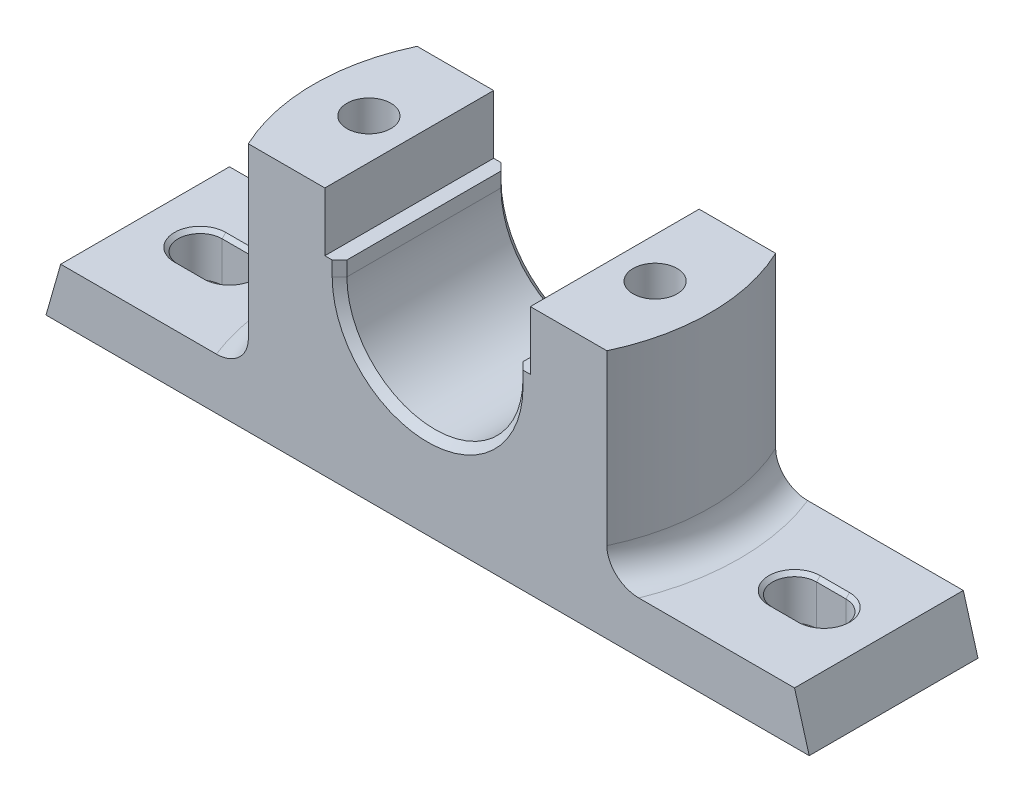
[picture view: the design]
ISO-10303-21;
HEADER;
FILE_DESCRIPTION(('STEP AP214'),'2;1');
FILE_NAME('part.step','',(''),(''),'','','');
FILE_SCHEMA(('AUTOMOTIVE_DESIGN { 1 0 10303 214 1 1 1 1 }'));
ENDSEC;
DATA;
#1=APPLICATION_CONTEXT('core data for automotive mechanical design processes');
#2=APPLICATION_PROTOCOL_DEFINITION('international standard','automotive_design',2000,#1);
#3=PRODUCT_CONTEXT('',#1,'mechanical');
#4=PRODUCT('Part','Part','',(#3));
#5=PRODUCT_RELATED_PRODUCT_CATEGORY('part','',(#4));
#6=PRODUCT_DEFINITION_FORMATION('','',#4);
#7=PRODUCT_DEFINITION_CONTEXT('part definition',#1,'design');
#8=PRODUCT_DEFINITION('design','',#6,#7);
#9=PRODUCT_DEFINITION_SHAPE('','',#8);
#10=(LENGTH_UNIT() NAMED_UNIT(*) SI_UNIT(.MILLI.,.METRE.));
#11=(NAMED_UNIT(*) PLANE_ANGLE_UNIT() SI_UNIT($,.RADIAN.));
#12=(NAMED_UNIT(*) SI_UNIT($,.STERADIAN.) SOLID_ANGLE_UNIT());
#13=UNCERTAINTY_MEASURE_WITH_UNIT(LENGTH_MEASURE(1.E-05),#10,'distance_accuracy_value','');
#14=(GEOMETRIC_REPRESENTATION_CONTEXT(3) GLOBAL_UNCERTAINTY_ASSIGNED_CONTEXT((#13)) GLOBAL_UNIT_ASSIGNED_CONTEXT((#10,
#11,#12)) REPRESENTATION_CONTEXT('',''));
#15=CARTESIAN_POINT('',(0.,0.,0.));
#16=DIRECTION('',(0.,0.,1.));
#17=DIRECTION('',(1.,0.,0.));
#18=AXIS2_PLACEMENT_3D('',#15,#16,#17);
#19=CARTESIAN_POINT('',(-97.5,2.,-17.5));
#20=DIRECTION('',(0.,-1.,0.));
#21=DIRECTION('',(0.,0.,-1.));
#22=AXIS2_PLACEMENT_3D('',#19,#20,#21);
#23=PLANE('',#22);
#24=CARTESIAN_POINT('',(85.,2.,0.));
#25=DIRECTION('',(0.,-1.,0.));
#26=DIRECTION('',(0.,0.,-1.));
#27=AXIS2_PLACEMENT_3D('',#24,#25,#26);
#28=CIRCLE('',#27,6.);
#29=CARTESIAN_POINT('',(85.,2.,-6.00000000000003));
#30=VERTEX_POINT('',#29);
#31=CARTESIAN_POINT('',(85.,2.,5.99999999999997));
#32=VERTEX_POINT('',#31);
#33=EDGE_CURVE('E338',#30,#32,#28,.T.);
#34=ORIENTED_EDGE('',*,*,#33,.F.);
#35=DIRECTION('',(1.,0.,0.));
#36=VECTOR('',#35,1.);
#37=CARTESIAN_POINT('',(-97.5,2.,-5.99999999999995));
#38=LINE('',#37,#36);
#39=CARTESIAN_POINT('',(77.,2.,-6.00000000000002));
#40=VERTEX_POINT('',#39);
#41=EDGE_CURVE('E320',#40,#30,#38,.T.);
#42=ORIENTED_EDGE('',*,*,#41,.F.);
#43=CARTESIAN_POINT('',(77.,2.,0.));
#44=DIRECTION('',(0.,-1.,0.));
#45=DIRECTION('',(0.,0.,-1.));
#46=AXIS2_PLACEMENT_3D('',#43,#44,#45);
#47=CIRCLE('',#46,6.);
#48=CARTESIAN_POINT('',(77.,2.,6.00000000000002));
#49=VERTEX_POINT('',#48);
#50=EDGE_CURVE('E332',#49,#40,#47,.T.);
#51=ORIENTED_EDGE('',*,*,#50,.F.);
#52=DIRECTION('',(-1.,0.,0.));
#53=VECTOR('',#52,1.);
#54=CARTESIAN_POINT('',(-97.5,2.,6.00000000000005));
#55=LINE('',#54,#53);
#56=EDGE_CURVE('E346',#32,#49,#55,.T.);
#57=ORIENTED_EDGE('',*,*,#56,.F.);
#58=EDGE_LOOP('',(#34,#42,#51,#57));
#59=FACE_BOUND('',#58,.T.);
#60=CARTESIAN_POINT('',(-77.,2.,0.));
#61=DIRECTION('',(0.,-1.,0.));
#62=DIRECTION('',(0.,0.,-1.));
#63=AXIS2_PLACEMENT_3D('',#60,#61,#62);
#64=CIRCLE('',#63,6.);
#65=CARTESIAN_POINT('',(-77.,2.,-6.));
#66=VERTEX_POINT('',#65);
#67=CARTESIAN_POINT('',(-77.,2.,6.));
#68=VERTEX_POINT('',#67);
#69=EDGE_CURVE('E370',#66,#68,#64,.T.);
#70=ORIENTED_EDGE('',*,*,#69,.F.);
#71=DIRECTION('',(1.,0.,0.));
#72=VECTOR('',#71,1.);
#73=CARTESIAN_POINT('',(-97.5,2.,-6.00000000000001));
#74=LINE('',#73,#72);
#75=CARTESIAN_POINT('',(-85.,2.,-6.00000000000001));
#76=VERTEX_POINT('',#75);
#77=EDGE_CURVE('E358',#76,#66,#74,.T.);
#78=ORIENTED_EDGE('',*,*,#77,.F.);
#79=CARTESIAN_POINT('',(-85.,2.,0.));
#80=DIRECTION('',(0.,-1.,0.));
#81=DIRECTION('',(0.,0.,-1.));
#82=AXIS2_PLACEMENT_3D('',#79,#80,#81);
#83=CIRCLE('',#82,6.);
#84=CARTESIAN_POINT('',(-85.,2.,5.99999999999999));
#85=VERTEX_POINT('',#84);
#86=EDGE_CURVE('E365',#85,#76,#83,.T.);
#87=ORIENTED_EDGE('',*,*,#86,.F.);
#88=DIRECTION('',(-1.,0.,0.));
#89=VECTOR('',#88,1.);
#90=CARTESIAN_POINT('',(-97.5,2.,5.99999999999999));
#91=LINE('',#90,#89);
#92=EDGE_CURVE('E368',#68,#85,#91,.T.);
#93=ORIENTED_EDGE('',*,*,#92,.F.);
#94=EDGE_LOOP('',(#70,#78,#87,#93));
#95=FACE_BOUND('',#94,.T.);
#96=DIRECTION('',(0.,0.,-1.));
#97=VECTOR('',#96,1.);
#98=CARTESIAN_POINT('',(-97.5,2.,17.5));
#99=LINE('',#98,#97);
#100=CARTESIAN_POINT('',(-97.5,2.,17.5));
#101=VERTEX_POINT('',#100);
#102=CARTESIAN_POINT('',(-97.5,2.,-17.5));
#103=VERTEX_POINT('',#102);
#104=EDGE_CURVE('E458',#101,#103,#99,.T.);
#105=ORIENTED_EDGE('',*,*,#104,.T.);
#106=DIRECTION('',(1.,0.,0.));
#107=VECTOR('',#106,1.);
#108=CARTESIAN_POINT('',(-97.5,2.,-17.5));
#109=LINE('',#108,#107);
#110=CARTESIAN_POINT('',(97.5,2.,-17.5));
#111=VERTEX_POINT('',#110);
#112=EDGE_CURVE('E461',#103,#111,#109,.T.);
#113=ORIENTED_EDGE('',*,*,#112,.T.);
#114=DIRECTION('',(0.,0.,1.));
#115=VECTOR('',#114,1.);
#116=CARTESIAN_POINT('',(97.5,2.,17.5));
#117=LINE('',#116,#115);
#118=CARTESIAN_POINT('',(97.5,2.,17.5));
#119=VERTEX_POINT('',#118);
#120=EDGE_CURVE('E464',#111,#119,#117,.T.);
#121=ORIENTED_EDGE('',*,*,#120,.T.);
#122=DIRECTION('',(-1.,0.,0.));
#123=VECTOR('',#122,1.);
#124=CARTESIAN_POINT('',(-97.5,2.,17.5));
#125=LINE('',#124,#123);
#126=EDGE_CURVE('E467',#119,#101,#125,.T.);
#127=ORIENTED_EDGE('',*,*,#126,.T.);
#128=EDGE_LOOP('',(#105,#113,#121,#127));
#129=FACE_BOUND('',#128,.T.);
#130=DIRECTION('',(0.,0.,-1.));
#131=VECTOR('',#130,1.);
#132=CARTESIAN_POINT('',(26.,2.,13.));
#133=LINE('',#132,#131);
#134=CARTESIAN_POINT('',(26.,2.,13.));
#135=VERTEX_POINT('',#134);
#136=CARTESIAN_POINT('',(26.,2.,-13.));
#137=VERTEX_POINT('',#136);
#138=EDGE_CURVE('E417',#135,#137,#133,.T.);
#139=ORIENTED_EDGE('',*,*,#138,.F.);
#140=DIRECTION('',(1.,0.,0.));
#141=VECTOR('',#140,1.);
#142=CARTESIAN_POINT('',(26.,2.,13.));
#143=LINE('',#142,#141);
#144=CARTESIAN_POINT('',(52.,2.,13.));
#145=VERTEX_POINT('',#144);
#146=EDGE_CURVE('E425',#135,#145,#143,.T.);
#147=ORIENTED_EDGE('',*,*,#146,.T.);
#148=DIRECTION('',(0.,0.,-1.));
#149=VECTOR('',#148,1.);
#150=CARTESIAN_POINT('',(52.,2.,13.));
#151=LINE('',#150,#149);
#152=CARTESIAN_POINT('',(52.,2.,-13.));
#153=VERTEX_POINT('',#152);
#154=EDGE_CURVE('E422',#145,#153,#151,.T.);
#155=ORIENTED_EDGE('',*,*,#154,.T.);
#156=DIRECTION('',(1.,0.,0.));
#157=VECTOR('',#156,1.);
#158=CARTESIAN_POINT('',(26.,2.,-13.));
#159=LINE('',#158,#157);
#160=EDGE_CURVE('E419',#137,#153,#159,.T.);
#161=ORIENTED_EDGE('',*,*,#160,.F.);
#162=EDGE_LOOP('',(#139,#147,#155,#161));
#163=FACE_BOUND('',#162,.T.);
#164=DIRECTION('',(-1.,0.,0.));
#165=VECTOR('',#164,1.);
#166=CARTESIAN_POINT('',(-26.,2.,13.));
#167=LINE('',#166,#165);
#168=CARTESIAN_POINT('',(-26.,2.,13.));
#169=VERTEX_POINT('',#168);
#170=CARTESIAN_POINT('',(-52.,2.,13.));
#171=VERTEX_POINT('',#170);
#172=EDGE_CURVE('E405',#169,#171,#167,.T.);
#173=ORIENTED_EDGE('',*,*,#172,.F.);
#174=DIRECTION('',(0.,0.,-1.));
#175=VECTOR('',#174,1.);
#176=CARTESIAN_POINT('',(-26.,2.,13.));
#177=LINE('',#176,#175);
#178=CARTESIAN_POINT('',(-26.,2.,-13.));
#179=VERTEX_POINT('',#178);
#180=EDGE_CURVE('E414',#169,#179,#177,.T.);
#181=ORIENTED_EDGE('',*,*,#180,.T.);
#182=DIRECTION('',(-1.,0.,0.));
#183=VECTOR('',#182,1.);
#184=CARTESIAN_POINT('',(-26.,2.,-13.));
#185=LINE('',#184,#183);
#186=CARTESIAN_POINT('',(-52.,2.,-13.));
#187=VERTEX_POINT('',#186);
#188=EDGE_CURVE('E411',#179,#187,#185,.T.);
#189=ORIENTED_EDGE('',*,*,#188,.T.);
#190=DIRECTION('',(0.,0.,-1.));
#191=VECTOR('',#190,1.);
#192=CARTESIAN_POINT('',(-52.,2.,13.));
#193=LINE('',#192,#191);
#194=EDGE_CURVE('E408',#171,#187,#193,.T.);
#195=ORIENTED_EDGE('',*,*,#194,.F.);
#196=EDGE_LOOP('',(#173,#181,#189,#195));
#197=FACE_BOUND('',#196,.T.);
#198=ADVANCED_FACE('F26',(#59,#95,#129,#163,#197),#23,.T.);
#199=CARTESIAN_POINT('',(54.,68.,23.));
#200=DIRECTION('',(0.,-1.,0.));
#201=DIRECTION('',(0.,0.,-1.));
#202=AXIS2_PLACEMENT_3D('',#199,#200,#201);
#203=PLANE('',#202);
#204=CARTESIAN_POINT('',(39.,68.,0.));
#205=DIRECTION('',(0.,-1.,0.));
#206=DIRECTION('',(0.,0.,-1.));
#207=AXIS2_PLACEMENT_3D('',#204,#205,#206);
#208=CIRCLE('',#207,6.);
#209=CARTESIAN_POINT('',(39.,68.,-6.));
#210=VERTEX_POINT('',#209);
#211=EDGE_CURVE('E375',#210,#210,#208,.T.);
#212=ORIENTED_EDGE('',*,*,#211,.T.);
#213=EDGE_LOOP('',(#212));
#214=FACE_BOUND('',#213,.T.);
#215=CARTESIAN_POINT('',(0.,68.,0.));
#216=DIRECTION('',(0.,1.,0.));
#217=DIRECTION('',(0.,0.,-1.));
#218=AXIS2_PLACEMENT_3D('',#215,#216,#217);
#219=CIRCLE('',#218,54.);
#220=CARTESIAN_POINT('',(48.8569340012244,68.,23.));
#221=VERTEX_POINT('',#220);
#222=CARTESIAN_POINT('',(48.8569340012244,68.,-23.));
#223=VERTEX_POINT('',#222);
#224=EDGE_CURVE('E480',#221,#223,#219,.T.);
#225=ORIENTED_EDGE('',*,*,#224,.T.);
#226=DIRECTION('',(-1.,0.,0.));
#227=VECTOR('',#226,1.);
#228=CARTESIAN_POINT('',(54.,68.,-23.));
#229=LINE('',#228,#227);
#230=CARTESIAN_POINT('',(28.,68.,-23.));
#231=VERTEX_POINT('',#230);
#232=EDGE_CURVE('E503',#223,#231,#229,.T.);
#233=ORIENTED_EDGE('',*,*,#232,.T.);
#234=DIRECTION('',(0.,0.,-1.));
#235=VECTOR('',#234,1.);
#236=CARTESIAN_POINT('',(28.,68.,23.));
#237=LINE('',#236,#235);
#238=CARTESIAN_POINT('',(28.,68.,23.));
#239=VERTEX_POINT('',#238);
#240=EDGE_CURVE('E569',#239,#231,#237,.T.);
#241=ORIENTED_EDGE('',*,*,#240,.F.);
#242=DIRECTION('',(-1.,0.,0.));
#243=VECTOR('',#242,1.);
#244=CARTESIAN_POINT('',(54.,68.,23.));
#245=LINE('',#244,#243);
#246=EDGE_CURVE('E529',#221,#239,#245,.T.);
#247=ORIENTED_EDGE('',*,*,#246,.F.);
#248=EDGE_LOOP('',(#225,#233,#241,#247));
#249=FACE_BOUND('',#248,.T.);
#250=ADVANCED_FACE('F694',(#214,#249),#203,.F.);
#251=CARTESIAN_POINT('',(-54.,68.,23.));
#252=DIRECTION('',(0.,-1.,0.));
#253=DIRECTION('',(1.,0.,0.));
#254=AXIS2_PLACEMENT_3D('',#251,#252,#253);
#255=PLANE('',#254);
#256=CARTESIAN_POINT('',(-39.,68.,0.));
#257=DIRECTION('',(0.,-1.,0.));
#258=DIRECTION('',(0.,0.,-1.));
#259=AXIS2_PLACEMENT_3D('',#256,#257,#258);
#260=CIRCLE('',#259,6.);
#261=CARTESIAN_POINT('',(-39.,68.,-6.00000000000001));
#262=VERTEX_POINT('',#261);
#263=EDGE_CURVE('E381',#262,#262,#260,.T.);
#264=ORIENTED_EDGE('',*,*,#263,.T.);
#265=EDGE_LOOP('',(#264));
#266=FACE_BOUND('',#265,.T.);
#267=CARTESIAN_POINT('',(0.,68.,0.));
#268=DIRECTION('',(0.,1.,0.));
#269=DIRECTION('',(0.,0.,1.));
#270=AXIS2_PLACEMENT_3D('',#267,#268,#269);
#271=CIRCLE('',#270,54.);
#272=CARTESIAN_POINT('',(-48.8569340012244,68.,-23.));
#273=VERTEX_POINT('',#272);
#274=CARTESIAN_POINT('',(-48.8569340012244,68.,23.));
#275=VERTEX_POINT('',#274);
#276=EDGE_CURVE('E485',#273,#275,#271,.T.);
#277=ORIENTED_EDGE('',*,*,#276,.T.);
#278=DIRECTION('',(-1.,0.,0.));
#279=VECTOR('',#278,1.);
#280=CARTESIAN_POINT('',(-54.,68.,23.));
#281=LINE('',#280,#279);
#282=CARTESIAN_POINT('',(-28.,68.,23.));
#283=VERTEX_POINT('',#282);
#284=EDGE_CURVE('E540',#283,#275,#281,.T.);
#285=ORIENTED_EDGE('',*,*,#284,.F.);
#286=DIRECTION('',(0.,0.,-1.));
#287=VECTOR('',#286,1.);
#288=CARTESIAN_POINT('',(-28.,68.,23.));
#289=LINE('',#288,#287);
#290=CARTESIAN_POINT('',(-28.,68.,-23.));
#291=VERTEX_POINT('',#290);
#292=EDGE_CURVE('E548',#283,#291,#289,.T.);
#293=ORIENTED_EDGE('',*,*,#292,.T.);
#294=DIRECTION('',(-1.,0.,0.));
#295=VECTOR('',#294,1.);
#296=CARTESIAN_POINT('',(-54.,68.,-23.));
#297=LINE('',#296,#295);
#298=EDGE_CURVE('E514',#291,#273,#297,.T.);
#299=ORIENTED_EDGE('',*,*,#298,.T.);
#300=EDGE_LOOP('',(#277,#285,#293,#299));
#301=FACE_BOUND('',#300,.T.);
#302=ADVANCED_FACE('F701',(#266,#301),#255,.F.);
#303=CARTESIAN_POINT('',(-104.,0.,23.));
#304=DIRECTION('',(0.961523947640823,-0.27472112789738,0.));
#305=DIRECTION('',(0.27472112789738,0.961523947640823,0.));
#306=AXIS2_PLACEMENT_3D('',#303,#304,#305);
#307=PLANE('',#306);
#308=DIRECTION('',(-0.27472112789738,-0.961523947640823,0.));
#309=VECTOR('',#308,1.);
#310=CARTESIAN_POINT('',(-104.,0.,-23.));
#311=LINE('',#310,#309);
#312=CARTESIAN_POINT('',(-100.,14.,-23.));
#313=VERTEX_POINT('',#312);
#314=CARTESIAN_POINT('',(-104.,0.,-23.));
#315=VERTEX_POINT('',#314);
#316=EDGE_CURVE('E493',#313,#315,#311,.T.);
#317=ORIENTED_EDGE('',*,*,#316,.T.);
#318=DIRECTION('',(0.,0.,-1.));
#319=VECTOR('',#318,1.);
#320=CARTESIAN_POINT('',(-104.,0.,23.));
#321=LINE('',#320,#319);
#322=CARTESIAN_POINT('',(-104.,0.,23.));
#323=VERTEX_POINT('',#322);
#324=EDGE_CURVE('E578',#323,#315,#321,.T.);
#325=ORIENTED_EDGE('',*,*,#324,.F.);
#326=DIRECTION('',(-0.27472112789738,-0.961523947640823,0.));
#327=VECTOR('',#326,1.);
#328=CARTESIAN_POINT('',(-104.,0.,23.));
#329=LINE('',#328,#327);
#330=CARTESIAN_POINT('',(-100.,14.,23.));
#331=VERTEX_POINT('',#330);
#332=EDGE_CURVE('E519',#331,#323,#329,.T.);
#333=ORIENTED_EDGE('',*,*,#332,.F.);
#334=DIRECTION('',(0.,0.,-1.));
#335=VECTOR('',#334,1.);
#336=CARTESIAN_POINT('',(-100.,14.,23.));
#337=LINE('',#336,#335);
#338=EDGE_CURVE('E545',#331,#313,#337,.T.);
#339=ORIENTED_EDGE('',*,*,#338,.T.);
#340=EDGE_LOOP('',(#317,#325,#333,#339));
#341=FACE_BOUND('',#340,.T.);
#342=ADVANCED_FACE('F28',(#341),#307,.F.);
#343=CARTESIAN_POINT('',(-104.,0.,23.));
#344=DIRECTION('',(0.,1.,0.));
#345=DIRECTION('',(0.,0.,1.));
#346=AXIS2_PLACEMENT_3D('',#343,#344,#345);
#347=PLANE('',#346);
#348=DIRECTION('',(1.,0.,0.));
#349=VECTOR('',#348,1.);
#350=CARTESIAN_POINT('',(-97.5,0.,-17.5));
#351=LINE('',#350,#349);
#352=CARTESIAN_POINT('',(-97.5,0.,-17.5));
#353=VERTEX_POINT('',#352);
#354=CARTESIAN_POINT('',(97.5,0.,-17.5));
#355=VERTEX_POINT('',#354);
#356=EDGE_CURVE('E449',#353,#355,#351,.T.);
#357=ORIENTED_EDGE('',*,*,#356,.F.);
#358=DIRECTION('',(0.,0.,-1.));
#359=VECTOR('',#358,1.);
#360=CARTESIAN_POINT('',(-97.5,0.,17.5));
#361=LINE('',#360,#359);
#362=CARTESIAN_POINT('',(-97.5,0.,17.5));
#363=VERTEX_POINT('',#362);
#364=EDGE_CURVE('E441',#363,#353,#361,.T.);
#365=ORIENTED_EDGE('',*,*,#364,.F.);
#366=DIRECTION('',(-1.,0.,0.));
#367=VECTOR('',#366,1.);
#368=CARTESIAN_POINT('',(-97.5,0.,17.5));
#369=LINE('',#368,#367);
#370=CARTESIAN_POINT('',(97.5,0.,17.5));
#371=VERTEX_POINT('',#370);
#372=EDGE_CURVE('E455',#371,#363,#369,.T.);
#373=ORIENTED_EDGE('',*,*,#372,.F.);
#374=DIRECTION('',(0.,0.,1.));
#375=VECTOR('',#374,1.);
#376=CARTESIAN_POINT('',(97.5,0.,17.5));
#377=LINE('',#376,#375);
#378=EDGE_CURVE('E452',#355,#371,#377,.T.);
#379=ORIENTED_EDGE('',*,*,#378,.F.);
#380=EDGE_LOOP('',(#357,#365,#373,#379));
#381=FACE_BOUND('',#380,.T.);
#382=DIRECTION('',(1.,0.,0.));
#383=VECTOR('',#382,1.);
#384=CARTESIAN_POINT('',(-104.,0.,-23.));
#385=LINE('',#384,#383);
#386=CARTESIAN_POINT('',(104.,0.,-23.));
#387=VERTEX_POINT('',#386);
#388=EDGE_CURVE('E496',#315,#387,#385,.T.);
#389=ORIENTED_EDGE('',*,*,#388,.T.);
#390=DIRECTION('',(0.,0.,-1.));
#391=VECTOR('',#390,1.);
#392=CARTESIAN_POINT('',(104.,0.,23.));
#393=LINE('',#392,#391);
#394=CARTESIAN_POINT('',(104.,0.,23.));
#395=VERTEX_POINT('',#394);
#396=EDGE_CURVE('E575',#395,#387,#393,.T.);
#397=ORIENTED_EDGE('',*,*,#396,.F.);
#398=DIRECTION('',(1.,0.,0.));
#399=VECTOR('',#398,1.);
#400=CARTESIAN_POINT('',(-104.,0.,23.));
#401=LINE('',#400,#399);
#402=EDGE_CURVE('E522',#323,#395,#401,.T.);
#403=ORIENTED_EDGE('',*,*,#402,.F.);
#404=ORIENTED_EDGE('',*,*,#324,.T.);
#405=EDGE_LOOP('',(#389,#397,#403,#404));
#406=FACE_BOUND('',#405,.T.);
#407=ADVANCED_FACE('F753',(#381,#406),#347,.F.);
#408=CARTESIAN_POINT('',(104.,0.,23.));
#409=DIRECTION('',(-0.961523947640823,-0.274721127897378,0.));
#410=DIRECTION('',(0.274721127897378,-0.961523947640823,0.));
#411=AXIS2_PLACEMENT_3D('',#408,#409,#410);
#412=PLANE('',#411);
#413=DIRECTION('',(-0.274721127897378,0.961523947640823,0.));
#414=VECTOR('',#413,1.);
#415=CARTESIAN_POINT('',(104.,0.,-23.));
#416=LINE('',#415,#414);
#417=CARTESIAN_POINT('',(100.,14.,-23.));
#418=VERTEX_POINT('',#417);
#419=EDGE_CURVE('E498',#387,#418,#416,.T.);
#420=ORIENTED_EDGE('',*,*,#419,.T.);
#421=DIRECTION('',(0.,0.,-1.));
#422=VECTOR('',#421,1.);
#423=CARTESIAN_POINT('',(100.,14.,23.));
#424=LINE('',#423,#422);
#425=CARTESIAN_POINT('',(100.,14.,23.));
#426=VERTEX_POINT('',#425);
#427=EDGE_CURVE('E572',#426,#418,#424,.T.);
#428=ORIENTED_EDGE('',*,*,#427,.F.);
#429=DIRECTION('',(-0.274721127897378,0.961523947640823,0.));
#430=VECTOR('',#429,1.);
#431=CARTESIAN_POINT('',(104.,0.,23.));
#432=LINE('',#431,#430);
#433=EDGE_CURVE('E524',#395,#426,#432,.T.);
#434=ORIENTED_EDGE('',*,*,#433,.F.);
#435=ORIENTED_EDGE('',*,*,#396,.T.);
#436=EDGE_LOOP('',(#420,#428,#434,#435));
#437=FACE_BOUND('',#436,.T.);
#438=ADVANCED_FACE('F756',(#437),#412,.F.);
#439=CARTESIAN_POINT('',(100.,14.,23.));
#440=DIRECTION('',(0.,-1.,0.));
#441=DIRECTION('',(1.,0.,0.));
#442=AXIS2_PLACEMENT_3D('',#439,#440,#441);
#443=PLANE('',#442);
#444=CARTESIAN_POINT('',(77.,14.,0.));
#445=DIRECTION('',(0.,-1.,0.));
#446=DIRECTION('',(1.,0.,0.));
#447=AXIS2_PLACEMENT_3D('',#444,#445,#446);
#448=CIRCLE('',#447,7.);
#449=CARTESIAN_POINT('',(77.,14.,6.99999999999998));
#450=VERTEX_POINT('',#449);
#451=CARTESIAN_POINT('',(77.,14.,-6.99999999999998));
#452=VERTEX_POINT('',#451);
#453=EDGE_CURVE('E885',#450,#452,#448,.T.);
#454=ORIENTED_EDGE('',*,*,#453,.T.);
#455=DIRECTION('',(1.,0.,0.));
#456=VECTOR('',#455,1.);
#457=CARTESIAN_POINT('',(100.,14.,-7.00000000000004));
#458=LINE('',#457,#456);
#459=CARTESIAN_POINT('',(85.,14.,-6.99999999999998));
#460=VERTEX_POINT('',#459);
#461=EDGE_CURVE('E889',#452,#460,#458,.T.);
#462=ORIENTED_EDGE('',*,*,#461,.T.);
#463=CARTESIAN_POINT('',(85.,14.,0.));
#464=DIRECTION('',(0.,-1.,0.));
#465=DIRECTION('',(1.,0.,0.));
#466=AXIS2_PLACEMENT_3D('',#463,#464,#465);
#467=CIRCLE('',#466,7.);
#468=CARTESIAN_POINT('',(85.,14.,6.99999999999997));
#469=VERTEX_POINT('',#468);
#470=EDGE_CURVE('E890',#460,#469,#467,.T.);
#471=ORIENTED_EDGE('',*,*,#470,.T.);
#472=DIRECTION('',(-1.,0.,0.));
#473=VECTOR('',#472,1.);
#474=CARTESIAN_POINT('',(100.,14.,6.99999999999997));
#475=LINE('',#474,#473);
#476=EDGE_CURVE('E893',#469,#450,#475,.T.);
#477=ORIENTED_EDGE('',*,*,#476,.T.);
#478=EDGE_LOOP('',(#454,#462,#471,#477));
#479=FACE_BOUND('',#478,.T.);
#480=DIRECTION('',(-1.,0.,0.));
#481=VECTOR('',#480,1.);
#482=CARTESIAN_POINT('',(100.,14.,-23.));
#483=LINE('',#482,#481);
#484=CARTESIAN_POINT('',(57.5760366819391,14.,-23.));
#485=VERTEX_POINT('',#484);
#486=EDGE_CURVE('E500',#418,#485,#483,.T.);
#487=ORIENTED_EDGE('',*,*,#486,.T.);
#488=CARTESIAN_POINT('',(0.,14.,0.));
#489=DIRECTION('',(0.,-1.,0.));
#490=DIRECTION('',(1.,0.,0.));
#491=AXIS2_PLACEMENT_3D('',#488,#489,#490);
#492=CIRCLE('',#491,62.);
#493=CARTESIAN_POINT('',(57.5760366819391,14.,23.));
#494=VERTEX_POINT('',#493);
#495=EDGE_CURVE('E589',#485,#494,#492,.T.);
#496=ORIENTED_EDGE('',*,*,#495,.T.);
#497=DIRECTION('',(-1.,0.,0.));
#498=VECTOR('',#497,1.);
#499=CARTESIAN_POINT('',(100.,14.,23.));
#500=LINE('',#499,#498);
#501=EDGE_CURVE('E526',#426,#494,#500,.T.);
#502=ORIENTED_EDGE('',*,*,#501,.F.);
#503=ORIENTED_EDGE('',*,*,#427,.T.);
#504=EDGE_LOOP('',(#487,#496,#502,#503));
#505=FACE_BOUND('',#504,.T.);
#506=ADVANCED_FACE('F760',(#479,#505),#443,.F.);
#507=CARTESIAN_POINT('',(28.,68.,23.));
#508=DIRECTION('',(1.,0.,0.));
#509=DIRECTION('',(0.,0.,-1.));
#510=AXIS2_PLACEMENT_3D('',#507,#508,#509);
#511=PLANE('',#510);
#512=DIRECTION('',(0.,-1.,0.));
#513=VECTOR('',#512,1.);
#514=CARTESIAN_POINT('',(28.,68.,-23.));
#515=LINE('',#514,#513);
#516=CARTESIAN_POINT('',(28.,52.,-23.));
#517=VERTEX_POINT('',#516);
#518=EDGE_CURVE('E505',#231,#517,#515,.T.);
#519=ORIENTED_EDGE('',*,*,#518,.T.);
#520=DIRECTION('',(0.,0.,-1.));
#521=VECTOR('',#520,1.);
#522=CARTESIAN_POINT('',(28.,52.,23.));
#523=LINE('',#522,#521);
#524=CARTESIAN_POINT('',(28.,52.,23.));
#525=VERTEX_POINT('',#524);
#526=EDGE_CURVE('E566',#525,#517,#523,.T.);
#527=ORIENTED_EDGE('',*,*,#526,.F.);
#528=DIRECTION('',(0.,-1.,0.));
#529=VECTOR('',#528,1.);
#530=CARTESIAN_POINT('',(28.,68.,23.));
#531=LINE('',#530,#529);
#532=EDGE_CURVE('E531',#239,#525,#531,.T.);
#533=ORIENTED_EDGE('',*,*,#532,.F.);
#534=ORIENTED_EDGE('',*,*,#240,.T.);
#535=EDGE_LOOP('',(#519,#527,#533,#534));
#536=FACE_BOUND('',#535,.T.);
#537=ADVANCED_FACE('F775',(#536),#511,.F.);
#538=CARTESIAN_POINT('',(28.,52.,23.));
#539=DIRECTION('',(0.,-1.,0.));
#540=DIRECTION('',(1.,0.,0.));
#541=AXIS2_PLACEMENT_3D('',#538,#539,#540);
#542=PLANE('',#541);
#543=DIRECTION('',(-1.,0.,0.));
#544=VECTOR('',#543,1.);
#545=CARTESIAN_POINT('',(28.,52.,-23.));
#546=LINE('',#545,#544);
#547=CARTESIAN_POINT('',(26.,52.,-23.));
#548=VERTEX_POINT('',#547);
#549=EDGE_CURVE('E507',#517,#548,#546,.T.);
#550=ORIENTED_EDGE('',*,*,#549,.T.);
#551=DIRECTION('',(0.707106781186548,0.,-0.707106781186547));
#552=VECTOR('',#551,1.);
#553=CARTESIAN_POINT('',(24.,52.,-21.));
#554=LINE('',#553,#552);
#555=CARTESIAN_POINT('',(24.,52.,-21.));
#556=VERTEX_POINT('',#555);
#557=EDGE_CURVE('E782',#548,#556,#554,.F.);
#558=ORIENTED_EDGE('',*,*,#557,.T.);
#559=DIRECTION('',(0.,0.,-1.));
#560=VECTOR('',#559,1.);
#561=CARTESIAN_POINT('',(24.,52.,23.));
#562=LINE('',#561,#560);
#563=CARTESIAN_POINT('',(24.,52.,21.));
#564=VERTEX_POINT('',#563);
#565=EDGE_CURVE('E563',#564,#556,#562,.T.);
#566=ORIENTED_EDGE('',*,*,#565,.F.);
#567=DIRECTION('',(0.707106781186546,0.,0.707106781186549));
#568=VECTOR('',#567,1.);
#569=CARTESIAN_POINT('',(26.,52.,23.));
#570=LINE('',#569,#568);
#571=CARTESIAN_POINT('',(26.,52.,23.));
#572=VERTEX_POINT('',#571);
#573=EDGE_CURVE('E779',#564,#572,#570,.T.);
#574=ORIENTED_EDGE('',*,*,#573,.T.);
#575=DIRECTION('',(-1.,0.,0.));
#576=VECTOR('',#575,1.);
#577=CARTESIAN_POINT('',(28.,52.,23.));
#578=LINE('',#577,#576);
#579=EDGE_CURVE('E533',#525,#572,#578,.T.);
#580=ORIENTED_EDGE('',*,*,#579,.F.);
#581=ORIENTED_EDGE('',*,*,#526,.T.);
#582=EDGE_LOOP('',(#550,#558,#566,#574,#580,#581));
#583=FACE_BOUND('',#582,.T.);
#584=ADVANCED_FACE('F1199',(#583),#542,.F.);
#585=CARTESIAN_POINT('',(24.,52.,23.));
#586=DIRECTION('',(1.,0.,0.));
#587=DIRECTION('',(0.,1.,0.));
#588=AXIS2_PLACEMENT_3D('',#585,#586,#587);
#589=PLANE('',#588);
#590=ORIENTED_EDGE('',*,*,#565,.T.);
#591=DIRECTION('',(0.,-1.,0.));
#592=VECTOR('',#591,1.);
#593=CARTESIAN_POINT('',(24.,52.,-21.));
#594=LINE('',#593,#592);
#595=CARTESIAN_POINT('',(24.,48.,-21.));
#596=VERTEX_POINT('',#595);
#597=EDGE_CURVE('E831',#556,#596,#594,.T.);
#598=ORIENTED_EDGE('',*,*,#597,.T.);
#599=DIRECTION('',(0.,0.,-1.));
#600=VECTOR('',#599,1.);
#601=CARTESIAN_POINT('',(24.,48.,23.));
#602=LINE('',#601,#600);
#603=CARTESIAN_POINT('',(24.,48.,21.));
#604=VERTEX_POINT('',#603);
#605=EDGE_CURVE('E560',#604,#596,#602,.T.);
#606=ORIENTED_EDGE('',*,*,#605,.F.);
#607=DIRECTION('',(0.,1.,0.));
#608=VECTOR('',#607,1.);
#609=CARTESIAN_POINT('',(24.,52.,21.));
#610=LINE('',#609,#608);
#611=EDGE_CURVE('E780',#604,#564,#610,.T.);
#612=ORIENTED_EDGE('',*,*,#611,.T.);
#613=EDGE_LOOP('',(#590,#598,#606,#612));
#614=FACE_BOUND('',#613,.T.);
#615=ADVANCED_FACE('F832',(#614),#589,.F.);
#616=CARTESIAN_POINT('',(0.,48.,23.));
#617=DIRECTION('',(0.,0.,-1.));
#618=DIRECTION('',(-1.,0.,0.));
#619=AXIS2_PLACEMENT_3D('',#616,#617,#618);
#620=CYLINDRICAL_SURFACE('',#619,24.);
#621=ORIENTED_EDGE('',*,*,#605,.T.);
#622=CARTESIAN_POINT('',(0.,48.,-21.));
#623=DIRECTION('',(0.,0.,1.));
#624=DIRECTION('',(1.,0.,0.));
#625=AXIS2_PLACEMENT_3D('',#622,#623,#624);
#626=CIRCLE('',#625,24.);
#627=CARTESIAN_POINT('',(-24.,48.,-21.));
#628=VERTEX_POINT('',#627);
#629=EDGE_CURVE('E800',#596,#628,#626,.F.);
#630=ORIENTED_EDGE('',*,*,#629,.T.);
#631=DIRECTION('',(0.,0.,-1.));
#632=VECTOR('',#631,1.);
#633=CARTESIAN_POINT('',(-24.,48.,23.));
#634=LINE('',#633,#632);
#635=CARTESIAN_POINT('',(-24.,48.,21.));
#636=VERTEX_POINT('',#635);
#637=EDGE_CURVE('E557',#636,#628,#634,.T.);
#638=ORIENTED_EDGE('',*,*,#637,.F.);
#639=CARTESIAN_POINT('',(0.,48.,21.));
#640=DIRECTION('',(0.,0.,1.));
#641=DIRECTION('',(1.,0.,0.));
#642=AXIS2_PLACEMENT_3D('',#639,#640,#641);
#643=CIRCLE('',#642,24.);
#644=EDGE_CURVE('E798',#636,#604,#643,.T.);
#645=ORIENTED_EDGE('',*,*,#644,.T.);
#646=EDGE_LOOP('',(#621,#630,#638,#645));
#647=FACE_BOUND('',#646,.T.);
#648=ADVANCED_FACE('F819',(#647),#620,.F.);
#649=CARTESIAN_POINT('',(-24.,52.,23.));
#650=DIRECTION('',(-1.,0.,0.));
#651=DIRECTION('',(0.,-1.,0.));
#652=AXIS2_PLACEMENT_3D('',#649,#650,#651);
#653=PLANE('',#652);
#654=ORIENTED_EDGE('',*,*,#637,.T.);
#655=DIRECTION('',(0.,1.,0.));
#656=VECTOR('',#655,1.);
#657=CARTESIAN_POINT('',(-24.,52.,-21.));
#658=LINE('',#657,#656);
#659=CARTESIAN_POINT('',(-24.,52.,-21.));
#660=VERTEX_POINT('',#659);
#661=EDGE_CURVE('E792',#628,#660,#658,.T.);
#662=ORIENTED_EDGE('',*,*,#661,.T.);
#663=DIRECTION('',(0.,0.,-1.));
#664=VECTOR('',#663,1.);
#665=CARTESIAN_POINT('',(-24.,52.,23.));
#666=LINE('',#665,#664);
#667=CARTESIAN_POINT('',(-24.,52.,21.));
#668=VERTEX_POINT('',#667);
#669=EDGE_CURVE('E554',#668,#660,#666,.T.);
#670=ORIENTED_EDGE('',*,*,#669,.F.);
#671=DIRECTION('',(0.,-1.,0.));
#672=VECTOR('',#671,1.);
#673=CARTESIAN_POINT('',(-24.,48.,21.));
#674=LINE('',#673,#672);
#675=EDGE_CURVE('E785',#668,#636,#674,.T.);
#676=ORIENTED_EDGE('',*,*,#675,.T.);
#677=EDGE_LOOP('',(#654,#662,#670,#676));
#678=FACE_BOUND('',#677,.T.);
#679=ADVANCED_FACE('F816',(#678),#653,.F.);
#680=CARTESIAN_POINT('',(-28.,52.,23.));
#681=DIRECTION('',(0.,-1.,0.));
#682=DIRECTION('',(1.,0.,0.));
#683=AXIS2_PLACEMENT_3D('',#680,#681,#682);
#684=PLANE('',#683);
#685=ORIENTED_EDGE('',*,*,#669,.T.);
#686=DIRECTION('',(0.707106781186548,0.,0.707106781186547));
#687=VECTOR('',#686,1.);
#688=CARTESIAN_POINT('',(-24.,52.,-21.));
#689=LINE('',#688,#687);
#690=CARTESIAN_POINT('',(-26.,52.,-23.));
#691=VERTEX_POINT('',#690);
#692=EDGE_CURVE('E796',#660,#691,#689,.F.);
#693=ORIENTED_EDGE('',*,*,#692,.T.);
#694=DIRECTION('',(-1.,0.,0.));
#695=VECTOR('',#694,1.);
#696=CARTESIAN_POINT('',(-28.,52.,-23.));
#697=LINE('',#696,#695);
#698=CARTESIAN_POINT('',(-28.,52.,-23.));
#699=VERTEX_POINT('',#698);
#700=EDGE_CURVE('E510',#691,#699,#697,.T.);
#701=ORIENTED_EDGE('',*,*,#700,.T.);
#702=DIRECTION('',(0.,0.,-1.));
#703=VECTOR('',#702,1.);
#704=CARTESIAN_POINT('',(-28.,52.,23.));
#705=LINE('',#704,#703);
#706=CARTESIAN_POINT('',(-28.,52.,23.));
#707=VERTEX_POINT('',#706);
#708=EDGE_CURVE('E551',#707,#699,#705,.T.);
#709=ORIENTED_EDGE('',*,*,#708,.F.);
#710=DIRECTION('',(-1.,0.,0.));
#711=VECTOR('',#710,1.);
#712=CARTESIAN_POINT('',(-28.,52.,23.));
#713=LINE('',#712,#711);
#714=CARTESIAN_POINT('',(-26.,52.,23.));
#715=VERTEX_POINT('',#714);
#716=EDGE_CURVE('E536',#715,#707,#713,.T.);
#717=ORIENTED_EDGE('',*,*,#716,.F.);
#718=DIRECTION('',(0.707106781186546,0.,-0.707106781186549));
#719=VECTOR('',#718,1.);
#720=CARTESIAN_POINT('',(-26.,52.,23.));
#721=LINE('',#720,#719);
#722=EDGE_CURVE('E794',#715,#668,#721,.T.);
#723=ORIENTED_EDGE('',*,*,#722,.T.);
#724=EDGE_LOOP('',(#685,#693,#701,#709,#717,#723));
#725=FACE_BOUND('',#724,.T.);
#726=ADVANCED_FACE('F808',(#725),#684,.F.);
#727=CARTESIAN_POINT('',(-28.,68.,23.));
#728=DIRECTION('',(-1.,0.,0.));
#729=DIRECTION('',(0.,0.,1.));
#730=AXIS2_PLACEMENT_3D('',#727,#728,#729);
#731=PLANE('',#730);
#732=DIRECTION('',(0.,1.,0.));
#733=VECTOR('',#732,1.);
#734=CARTESIAN_POINT('',(-28.,68.,-23.));
#735=LINE('',#734,#733);
#736=EDGE_CURVE('E512',#699,#291,#735,.T.);
#737=ORIENTED_EDGE('',*,*,#736,.T.);
#738=ORIENTED_EDGE('',*,*,#292,.F.);
#739=DIRECTION('',(0.,1.,0.));
#740=VECTOR('',#739,1.);
#741=CARTESIAN_POINT('',(-28.,68.,23.));
#742=LINE('',#741,#740);
#743=EDGE_CURVE('E538',#707,#283,#742,.T.);
#744=ORIENTED_EDGE('',*,*,#743,.F.);
#745=ORIENTED_EDGE('',*,*,#708,.T.);
#746=EDGE_LOOP('',(#737,#738,#744,#745));
#747=FACE_BOUND('',#746,.T.);
#748=ADVANCED_FACE('F1179',(#747),#731,.F.);
#749=CARTESIAN_POINT('',(-100.,14.,23.));
#750=DIRECTION('',(0.,-1.,0.));
#751=DIRECTION('',(1.,0.,0.));
#752=AXIS2_PLACEMENT_3D('',#749,#750,#751);
#753=PLANE('',#752);
#754=CARTESIAN_POINT('',(-85.,14.,0.));
#755=DIRECTION('',(0.,-1.,0.));
#756=DIRECTION('',(1.,0.,0.));
#757=AXIS2_PLACEMENT_3D('',#754,#755,#756);
#758=CIRCLE('',#757,6.99999999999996);
#759=CARTESIAN_POINT('',(-85.,14.,6.99999999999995));
#760=VERTEX_POINT('',#759);
#761=CARTESIAN_POINT('',(-85.,14.,-6.99999999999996));
#762=VERTEX_POINT('',#761);
#763=EDGE_CURVE('E910',#760,#762,#758,.T.);
#764=ORIENTED_EDGE('',*,*,#763,.T.);
#765=DIRECTION('',(1.,0.,0.));
#766=VECTOR('',#765,1.);
#767=CARTESIAN_POINT('',(-100.,14.,-6.99999999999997));
#768=LINE('',#767,#766);
#769=CARTESIAN_POINT('',(-77.,14.,-6.99999999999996));
#770=VERTEX_POINT('',#769);
#771=EDGE_CURVE('E907',#762,#770,#768,.T.);
#772=ORIENTED_EDGE('',*,*,#771,.T.);
#773=CARTESIAN_POINT('',(-77.,14.,0.));
#774=DIRECTION('',(0.,-1.,0.));
#775=DIRECTION('',(1.,0.,0.));
#776=AXIS2_PLACEMENT_3D('',#773,#774,#775);
#777=CIRCLE('',#776,6.99999999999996);
#778=CARTESIAN_POINT('',(-77.,14.,6.99999999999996));
#779=VERTEX_POINT('',#778);
#780=EDGE_CURVE('E912',#770,#779,#777,.T.);
#781=ORIENTED_EDGE('',*,*,#780,.T.);
#782=DIRECTION('',(-1.,0.,0.));
#783=VECTOR('',#782,1.);
#784=CARTESIAN_POINT('',(-100.,14.,6.99999999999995));
#785=LINE('',#784,#783);
#786=EDGE_CURVE('E913',#779,#760,#785,.T.);
#787=ORIENTED_EDGE('',*,*,#786,.T.);
#788=EDGE_LOOP('',(#764,#772,#781,#787));
#789=FACE_BOUND('',#788,.T.);
#790=DIRECTION('',(-1.,0.,0.));
#791=VECTOR('',#790,1.);
#792=CARTESIAN_POINT('',(-100.,14.,23.));
#793=LINE('',#792,#791);
#794=CARTESIAN_POINT('',(-57.5760366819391,14.,23.));
#795=VERTEX_POINT('',#794);
#796=EDGE_CURVE('E543',#795,#331,#793,.T.);
#797=ORIENTED_EDGE('',*,*,#796,.F.);
#798=CARTESIAN_POINT('',(0.,14.,0.));
#799=DIRECTION('',(0.,-1.,0.));
#800=DIRECTION('',(1.,0.,0.));
#801=AXIS2_PLACEMENT_3D('',#798,#799,#800);
#802=CIRCLE('',#801,62.);
#803=CARTESIAN_POINT('',(-57.5760366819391,14.,-23.));
#804=VERTEX_POINT('',#803);
#805=EDGE_CURVE('E584',#795,#804,#802,.T.);
#806=ORIENTED_EDGE('',*,*,#805,.T.);
#807=DIRECTION('',(-1.,0.,0.));
#808=VECTOR('',#807,1.);
#809=CARTESIAN_POINT('',(-100.,14.,-23.));
#810=LINE('',#809,#808);
#811=EDGE_CURVE('E517',#804,#313,#810,.T.);
#812=ORIENTED_EDGE('',*,*,#811,.T.);
#813=ORIENTED_EDGE('',*,*,#338,.F.);
#814=EDGE_LOOP('',(#797,#806,#812,#813));
#815=FACE_BOUND('',#814,.T.);
#816=ADVANCED_FACE('F613',(#789,#815),#753,.F.);
#817=CARTESIAN_POINT('',(0.,48.,23.));
#818=DIRECTION('',(0.,0.,1.));
#819=DIRECTION('',(1.,0.,0.));
#820=AXIS2_PLACEMENT_3D('',#817,#818,#819);
#821=PLANE('',#820);
#822=ORIENTED_EDGE('',*,*,#579,.T.);
#823=DIRECTION('',(0.,-1.,0.));
#824=VECTOR('',#823,1.);
#825=CARTESIAN_POINT('',(26.,48.,23.));
#826=LINE('',#825,#824);
#827=CARTESIAN_POINT('',(26.,48.,23.));
#828=VERTEX_POINT('',#827);
#829=EDGE_CURVE('E11',#572,#828,#826,.T.);
#830=ORIENTED_EDGE('',*,*,#829,.T.);
#831=CARTESIAN_POINT('',(0.,48.,23.));
#832=DIRECTION('',(0.,0.,1.));
#833=DIRECTION('',(1.,0.,0.));
#834=AXIS2_PLACEMENT_3D('',#831,#832,#833);
#835=CIRCLE('',#834,26.);
#836=CARTESIAN_POINT('',(-26.,48.,23.));
#837=VERTEX_POINT('',#836);
#838=EDGE_CURVE('E40',#828,#837,#835,.F.);
#839=ORIENTED_EDGE('',*,*,#838,.T.);
#840=DIRECTION('',(0.,1.,0.));
#841=VECTOR('',#840,1.);
#842=CARTESIAN_POINT('',(-26.,52.,23.));
#843=LINE('',#842,#841);
#844=EDGE_CURVE('E34',#837,#715,#843,.T.);
#845=ORIENTED_EDGE('',*,*,#844,.T.);
#846=ORIENTED_EDGE('',*,*,#716,.T.);
#847=ORIENTED_EDGE('',*,*,#743,.T.);
#848=ORIENTED_EDGE('',*,*,#284,.T.);
#849=DIRECTION('',(0.,1.,0.));
#850=VECTOR('',#849,1.);
#851=CARTESIAN_POINT('',(-48.8569340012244,-999932.,23.));
#852=LINE('',#851,#850);
#853=CARTESIAN_POINT('',(-48.8569340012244,22.0000000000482,23.));
#854=VERTEX_POINT('',#853);
#855=EDGE_CURVE('E483',#854,#275,#852,.T.);
#856=ORIENTED_EDGE('',*,*,#855,.F.);
#857=CARTESIAN_POINT('',(-48.8569340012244,22.0000000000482,23.));
#858=CARTESIAN_POINT('',(-48.8568944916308,21.7897037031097,23.));
#859=CARTESIAN_POINT('',(-48.8660972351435,21.5794200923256,23.));
#860=CARTESIAN_POINT('',(-48.9026955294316,21.1604976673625,23.));
#861=CARTESIAN_POINT('',(-48.9300861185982,20.9518584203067,23.));
#862=CARTESIAN_POINT('',(-49.0026422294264,20.5384483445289,23.));
#863=CARTESIAN_POINT('',(-49.0477455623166,20.3336665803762,23.));
#864=CARTESIAN_POINT('',(-49.1551914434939,19.9286763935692,23.));
#865=CARTESIAN_POINT('',(-49.2175345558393,19.7284681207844,23.));
#866=CARTESIAN_POINT('',(-49.3587056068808,19.3341515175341,23.));
#867=CARTESIAN_POINT('',(-49.4375194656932,19.1400381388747,23.));
#868=CARTESIAN_POINT('',(-49.6108643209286,18.7588835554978,23.));
#869=CARTESIAN_POINT('',(-49.7054011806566,18.5718450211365,23.));
#870=CARTESIAN_POINT('',(-49.909260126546,18.2059678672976,23.));
#871=CARTESIAN_POINT('',(-50.0185851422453,18.0271308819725,23.));
#872=CARTESIAN_POINT('',(-50.251044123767,17.6785870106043,23.));
#873=CARTESIAN_POINT('',(-50.3741833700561,17.5088836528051,23.));
#874=CARTESIAN_POINT('',(-50.6386238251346,17.172609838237,23.));
#875=CARTESIAN_POINT('',(-50.7804689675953,17.0064666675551,23.));
#876=CARTESIAN_POINT('',(-51.0768009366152,16.6858302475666,23.));
#877=CARTESIAN_POINT('',(-51.2312923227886,16.531341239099,23.));
#878=CARTESIAN_POINT('',(-51.7119073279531,16.0864805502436,23.));
#879=CARTESIAN_POINT('',(-52.0553511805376,15.8144890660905,23.));
#880=CARTESIAN_POINT('',(-52.8107494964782,15.3025371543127,23.));
#881=CARTESIAN_POINT('',(-53.2260819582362,15.0675926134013,23.));
#882=CARTESIAN_POINT('',(-54.0883596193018,14.6652815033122,23.));
#883=CARTESIAN_POINT('',(-54.5353157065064,14.4979383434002,23.));
#884=CARTESIAN_POINT('',(-55.4119481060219,14.2445948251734,23.));
#885=CARTESIAN_POINT('',(-55.840017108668,14.1530314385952,23.));
#886=CARTESIAN_POINT('',(-56.48803719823,14.0613163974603,23.));
#887=CARTESIAN_POINT('',(-56.7049685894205,14.0383497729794,23.));
#888=CARTESIAN_POINT('',(-57.1399216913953,14.0076931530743,23.));
#889=CARTESIAN_POINT('',(-57.3579434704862,14.0000041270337,23.));
#890=CARTESIAN_POINT('',(-57.5760366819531,14.0000000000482,23.));
#891=B_SPLINE_CURVE_WITH_KNOTS('',3,(#857,#858,#859,#860,#861,#862,#863,#864,#865,#866,#867,
#868,#869,#870,#871,#872,#873,#874,#875,#876,#877,#878,#879,#880,#881,#882,#883,#884,#885,#886,
#887,#888,#889,#890),.UNSPECIFIED.,.F.,.F.,(4,2,2,2,2,2,2,2,2,2,2,2,2,2,2,2,4),(0.,
0.630667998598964,1.26116402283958,1.88946591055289,2.51778835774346,3.14557586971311,
3.77359801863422,4.40174476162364,5.03013243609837,5.68478012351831,6.33966489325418,
7.64857785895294,9.07415774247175,10.5002308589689,11.8088856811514,12.4628479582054,
13.1168517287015),.UNSPECIFIED.);
#892=EDGE_CURVE('E591',#854,#795,#891,.T.);
#893=ORIENTED_EDGE('',*,*,#892,.T.);
#894=ORIENTED_EDGE('',*,*,#796,.T.);
#895=ORIENTED_EDGE('',*,*,#332,.T.);
#896=ORIENTED_EDGE('',*,*,#402,.T.);
#897=ORIENTED_EDGE('',*,*,#433,.T.);
#898=ORIENTED_EDGE('',*,*,#501,.T.);
#899=CARTESIAN_POINT('',(57.5760366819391,14.,23.));
#900=CARTESIAN_POINT('',(57.3157465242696,13.9999861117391,23.));
#901=CARTESIAN_POINT('',(57.0554642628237,14.0109545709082,23.));
#902=CARTESIAN_POINT('',(56.5367274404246,14.0546304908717,23.));
#903=CARTESIAN_POINT('',(56.2782728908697,14.0873380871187,23.));
#904=CARTESIAN_POINT('',(55.7647130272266,14.1743163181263,23.));
#905=CARTESIAN_POINT('',(55.5096118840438,14.2286115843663,23.));
#906=CARTESIAN_POINT('',(55.0048736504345,14.358443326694,23.));
#907=CARTESIAN_POINT('',(54.7552364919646,14.4339795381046,23.));
#908=CARTESIAN_POINT('',(54.2630898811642,14.6059576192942,23.));
#909=CARTESIAN_POINT('',(54.0205849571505,14.7024124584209,23.));
#910=CARTESIAN_POINT('',(53.5446290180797,14.9157643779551,23.));
#911=CARTESIAN_POINT('',(53.3111812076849,15.032668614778,23.));
#912=CARTESIAN_POINT('',(52.8554559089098,15.2862486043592,23.));
#913=CARTESIAN_POINT('',(52.633171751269,15.4229123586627,23.));
#914=CARTESIAN_POINT('',(52.2015693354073,15.7153670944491,23.));
#915=CARTESIAN_POINT('',(51.9922500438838,15.8711565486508,23.));
#916=CARTESIAN_POINT('',(51.5944194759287,16.1962302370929,23.));
#917=CARTESIAN_POINT('',(51.4054800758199,16.3649902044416,23.));
#918=CARTESIAN_POINT('',(51.0436072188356,16.7187493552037,23.));
#919=CARTESIAN_POINT('',(50.8706666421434,16.9037412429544,23.));
#920=CARTESIAN_POINT('',(50.5425384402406,17.2889300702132,23.));
#921=CARTESIAN_POINT('',(50.3873540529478,17.4891297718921,23.));
#922=CARTESIAN_POINT('',(50.0966425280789,17.9033214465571,23.));
#923=CARTESIAN_POINT('',(49.9611128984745,18.1173116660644,23.));
#924=CARTESIAN_POINT('',(49.7218092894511,18.539238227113,23.));
#925=CARTESIAN_POINT('',(49.6163360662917,18.7462117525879,23.));
#926=CARTESIAN_POINT('',(49.4246955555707,19.1689008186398,23.));
#927=CARTESIAN_POINT('',(49.3385256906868,19.3846151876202,23.));
#928=CARTESIAN_POINT('',(49.186731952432,19.8227435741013,23.));
#929=CARTESIAN_POINT('',(49.121072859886,20.0451453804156,23.));
#930=CARTESIAN_POINT('',(49.0110307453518,20.4950496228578,23.));
#931=CARTESIAN_POINT('',(48.9666359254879,20.7225491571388,23.));
#932=CARTESIAN_POINT('',(48.9078153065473,21.125255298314,23.));
#933=CARTESIAN_POINT('',(48.8887373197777,21.2997960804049,23.));
#934=CARTESIAN_POINT('',(48.8632978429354,21.6495508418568,23.));
#935=CARTESIAN_POINT('',(48.8569182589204,21.8247635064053,23.));
#936=CARTESIAN_POINT('',(48.8569340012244,22.0000000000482,23.));
#937=B_SPLINE_CURVE_WITH_KNOTS('',3,(#899,#900,#901,#902,#903,#904,#905,#906,#907,#908,#909,
#910,#911,#912,#913,#914,#915,#916,#917,#918,#919,#920,#921,#922,#923,#924,#925,#926,#927,#928,
#929,#930,#931,#932,#933,#934,#935,#936),.UNSPECIFIED.,.F.,.F.,(4,2,2,2,2,2,2,2,2,2,2,2,2,2,2,2,
2,2,4),(0.,0.780629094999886,1.56126305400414,2.34279028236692,3.12430777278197,
3.90631118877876,4.68858882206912,5.47039341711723,6.25213562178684,7.01114143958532,
7.76980784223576,8.52861237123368,9.28732060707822,9.98328546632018,10.6791573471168,
11.373827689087,12.0681121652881,12.5944106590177,13.1199586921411),.UNSPECIFIED.);
#938=CARTESIAN_POINT('',(48.8569340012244,22.0000000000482,23.));
#939=VERTEX_POINT('',#938);
#940=EDGE_CURVE('E619',#494,#939,#937,.T.);
#941=ORIENTED_EDGE('',*,*,#940,.T.);
#942=DIRECTION('',(0.,1.,0.));
#943=VECTOR('',#942,1.);
#944=CARTESIAN_POINT('',(48.8569340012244,-999932.,23.));
#945=LINE('',#944,#943);
#946=EDGE_CURVE('E484',#939,#221,#945,.T.);
#947=ORIENTED_EDGE('',*,*,#946,.T.);
#948=ORIENTED_EDGE('',*,*,#246,.T.);
#949=ORIENTED_EDGE('',*,*,#532,.T.);
#950=EDGE_LOOP('',(#822,#830,#839,#845,#846,#847,#848,#856,#893,#894,#895,#896,#897,#898,#941,
#947,#948,#949));
#951=FACE_BOUND('',#950,.T.);
#952=ADVANCED_FACE('F608',(#951),#821,.T.);
#953=CARTESIAN_POINT('',(0.,48.,-23.));
#954=DIRECTION('',(0.,0.,1.));
#955=DIRECTION('',(1.,0.,0.));
#956=AXIS2_PLACEMENT_3D('',#953,#954,#955);
#957=PLANE('',#956);
#958=CARTESIAN_POINT('',(0.,48.,-23.));
#959=DIRECTION('',(0.,0.,1.));
#960=DIRECTION('',(1.,0.,0.));
#961=AXIS2_PLACEMENT_3D('',#958,#959,#960);
#962=CIRCLE('',#961,26.);
#963=CARTESIAN_POINT('',(-26.,48.,-23.));
#964=VERTEX_POINT('',#963);
#965=CARTESIAN_POINT('',(26.,48.,-23.));
#966=VERTEX_POINT('',#965);
#967=EDGE_CURVE('E834',#964,#966,#962,.T.);
#968=ORIENTED_EDGE('',*,*,#967,.T.);
#969=DIRECTION('',(0.,1.,0.));
#970=VECTOR('',#969,1.);
#971=CARTESIAN_POINT('',(26.,48.,-23.));
#972=LINE('',#971,#970);
#973=EDGE_CURVE('E783',#966,#548,#972,.T.);
#974=ORIENTED_EDGE('',*,*,#973,.T.);
#975=ORIENTED_EDGE('',*,*,#549,.F.);
#976=ORIENTED_EDGE('',*,*,#518,.F.);
#977=ORIENTED_EDGE('',*,*,#232,.F.);
#978=DIRECTION('',(0.,1.,0.));
#979=VECTOR('',#978,1.);
#980=CARTESIAN_POINT('',(48.8569340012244,-999932.,-23.));
#981=LINE('',#980,#979);
#982=CARTESIAN_POINT('',(48.8569340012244,22.0000000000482,-23.));
#983=VERTEX_POINT('',#982);
#984=EDGE_CURVE('E488',#983,#223,#981,.T.);
#985=ORIENTED_EDGE('',*,*,#984,.F.);
#986=CARTESIAN_POINT('',(48.8569340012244,22.0000000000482,-23.));
#987=CARTESIAN_POINT('',(48.8568944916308,21.7897037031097,-23.));
#988=CARTESIAN_POINT('',(48.8660972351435,21.5794200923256,-23.));
#989=CARTESIAN_POINT('',(48.9026955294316,21.1604976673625,-23.));
#990=CARTESIAN_POINT('',(48.9300861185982,20.9518584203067,-23.));
#991=CARTESIAN_POINT('',(49.0026422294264,20.5384483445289,-23.));
#992=CARTESIAN_POINT('',(49.0477455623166,20.3336665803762,-23.));
#993=CARTESIAN_POINT('',(49.1551914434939,19.9286763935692,-23.));
#994=CARTESIAN_POINT('',(49.2175345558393,19.7284681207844,-23.));
#995=CARTESIAN_POINT('',(49.3587056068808,19.3341515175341,-23.));
#996=CARTESIAN_POINT('',(49.4375194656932,19.1400381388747,-23.));
#997=CARTESIAN_POINT('',(49.6108643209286,18.7588835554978,-23.));
#998=CARTESIAN_POINT('',(49.7054011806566,18.5718450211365,-23.));
#999=CARTESIAN_POINT('',(49.9092601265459,18.2059678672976,-23.));
#1000=CARTESIAN_POINT('',(50.0185851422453,18.0271308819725,-23.));
#1001=CARTESIAN_POINT('',(50.251044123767,17.6785870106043,-23.));
#1002=CARTESIAN_POINT('',(50.3741833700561,17.5088836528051,-23.));
#1003=CARTESIAN_POINT('',(50.6386238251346,17.172609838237,-23.));
#1004=CARTESIAN_POINT('',(50.7804689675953,17.0064666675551,-23.));
#1005=CARTESIAN_POINT('',(51.0768009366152,16.6858302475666,-23.));
#1006=CARTESIAN_POINT('',(51.2312923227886,16.531341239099,-23.));
#1007=CARTESIAN_POINT('',(51.7119073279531,16.0864805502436,-23.));
#1008=CARTESIAN_POINT('',(52.0553511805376,15.8144890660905,-23.));
#1009=CARTESIAN_POINT('',(52.8107494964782,15.3025371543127,-23.));
#1010=CARTESIAN_POINT('',(53.2260819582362,15.0675926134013,-23.));
#1011=CARTESIAN_POINT('',(54.0883596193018,14.6652815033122,-23.));
#1012=CARTESIAN_POINT('',(54.5353157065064,14.4979383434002,-23.));
#1013=CARTESIAN_POINT('',(55.4119481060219,14.2445948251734,-23.));
#1014=CARTESIAN_POINT('',(55.840017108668,14.1530314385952,-23.));
#1015=CARTESIAN_POINT('',(56.48803719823,14.0613163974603,-23.));
#1016=CARTESIAN_POINT('',(56.7049685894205,14.0383497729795,-23.));
#1017=CARTESIAN_POINT('',(57.1399216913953,14.0076931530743,-23.));
#1018=CARTESIAN_POINT('',(57.3579434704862,14.0000041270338,-23.));
#1019=CARTESIAN_POINT('',(57.5760366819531,14.0000000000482,-23.));
#1020=B_SPLINE_CURVE_WITH_KNOTS('',3,(#986,#987,#988,#989,#990,#991,#992,#993,#994,#995,#996,
#997,#998,#999,#1000,#1001,#1002,#1003,#1004,#1005,#1006,#1007,#1008,#1009,#1010,#1011,#1012,
#1013,#1014,#1015,#1016,#1017,#1018,#1019),.UNSPECIFIED.,.F.,.F.,(4,2,2,2,2,2,2,2,2,2,2,2,2,2,2,
2,4),(0.,0.630667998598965,1.26116402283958,1.88946591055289,2.51778835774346,3.14557586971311,
3.77359801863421,4.40174476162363,5.03013243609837,5.68478012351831,6.33966489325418,
7.64857785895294,9.07415774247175,10.5002308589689,11.8088856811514,12.4628479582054,
13.1168517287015),.UNSPECIFIED.);
#1021=EDGE_CURVE('E625',#983,#485,#1020,.T.);
#1022=ORIENTED_EDGE('',*,*,#1021,.T.);
#1023=ORIENTED_EDGE('',*,*,#486,.F.);
#1024=ORIENTED_EDGE('',*,*,#419,.F.);
#1025=ORIENTED_EDGE('',*,*,#388,.F.);
#1026=ORIENTED_EDGE('',*,*,#316,.F.);
#1027=ORIENTED_EDGE('',*,*,#811,.F.);
#1028=CARTESIAN_POINT('',(-57.5760366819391,14.,-23.));
#1029=CARTESIAN_POINT('',(-57.3157465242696,13.9999861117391,-23.));
#1030=CARTESIAN_POINT('',(-57.0554642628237,14.0109545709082,-23.));
#1031=CARTESIAN_POINT('',(-56.5367274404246,14.0546304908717,-23.));
#1032=CARTESIAN_POINT('',(-56.2782728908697,14.0873380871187,-23.));
#1033=CARTESIAN_POINT('',(-55.7647130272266,14.1743163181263,-23.));
#1034=CARTESIAN_POINT('',(-55.5096118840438,14.2286115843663,-23.));
#1035=CARTESIAN_POINT('',(-55.0048736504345,14.358443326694,-23.));
#1036=CARTESIAN_POINT('',(-54.7552364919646,14.4339795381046,-23.));
#1037=CARTESIAN_POINT('',(-54.2630898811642,14.6059576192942,-23.));
#1038=CARTESIAN_POINT('',(-54.0205849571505,14.7024124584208,-23.));
#1039=CARTESIAN_POINT('',(-53.5446290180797,14.9157643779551,-23.));
#1040=CARTESIAN_POINT('',(-53.3111812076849,15.032668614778,-23.));
#1041=CARTESIAN_POINT('',(-52.8554559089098,15.2862486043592,-23.));
#1042=CARTESIAN_POINT('',(-52.633171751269,15.4229123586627,-23.));
#1043=CARTESIAN_POINT('',(-52.2015693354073,15.7153670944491,-23.));
#1044=CARTESIAN_POINT('',(-51.9922500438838,15.8711565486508,-23.));
#1045=CARTESIAN_POINT('',(-51.5944194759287,16.1962302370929,-23.));
#1046=CARTESIAN_POINT('',(-51.4054800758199,16.3649902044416,-23.));
#1047=CARTESIAN_POINT('',(-51.0436072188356,16.7187493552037,-23.));
#1048=CARTESIAN_POINT('',(-50.8706666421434,16.9037412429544,-23.));
#1049=CARTESIAN_POINT('',(-50.5425384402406,17.2889300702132,-23.));
#1050=CARTESIAN_POINT('',(-50.3873540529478,17.4891297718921,-23.));
#1051=CARTESIAN_POINT('',(-50.0966425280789,17.9033214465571,-23.));
#1052=CARTESIAN_POINT('',(-49.9611128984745,18.1173116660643,-23.));
#1053=CARTESIAN_POINT('',(-49.7218092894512,18.539238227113,-23.));
#1054=CARTESIAN_POINT('',(-49.6163360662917,18.7462117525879,-23.));
#1055=CARTESIAN_POINT('',(-49.4246955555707,19.1689008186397,-23.));
#1056=CARTESIAN_POINT('',(-49.3385256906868,19.3846151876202,-23.));
#1057=CARTESIAN_POINT('',(-49.186731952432,19.8227435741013,-23.));
#1058=CARTESIAN_POINT('',(-49.121072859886,20.0451453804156,-23.));
#1059=CARTESIAN_POINT('',(-49.0110307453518,20.4950496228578,-23.));
#1060=CARTESIAN_POINT('',(-48.9666359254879,20.7225491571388,-23.));
#1061=CARTESIAN_POINT('',(-48.9078153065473,21.125255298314,-23.));
#1062=CARTESIAN_POINT('',(-48.8887373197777,21.2997960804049,-23.));
#1063=CARTESIAN_POINT('',(-48.8632978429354,21.6495508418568,-23.));
#1064=CARTESIAN_POINT('',(-48.8569182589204,21.8247635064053,-23.));
#1065=CARTESIAN_POINT('',(-48.8569340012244,22.0000000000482,-23.));
#1066=B_SPLINE_CURVE_WITH_KNOTS('',3,(#1028,#1029,#1030,#1031,#1032,#1033,#1034,#1035,#1036,
#1037,#1038,#1039,#1040,#1041,#1042,#1043,#1044,#1045,#1046,#1047,#1048,#1049,#1050,#1051,#1052,
#1053,#1054,#1055,#1056,#1057,#1058,#1059,#1060,#1061,#1062,#1063,#1064,#1065),.UNSPECIFIED.,
.F.,.F.,(4,2,2,2,2,2,2,2,2,2,2,2,2,2,2,2,2,2,4),(0.,0.780629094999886,1.56126305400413,
2.3427902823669,3.12430777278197,3.90631118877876,4.68858882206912,5.47039341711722,
6.25213562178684,7.01114143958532,7.76980784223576,8.52861237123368,9.28732060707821,
9.98328546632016,10.6791573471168,11.373827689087,12.0681121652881,12.5944106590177,
13.1199586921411),.UNSPECIFIED.);
#1067=CARTESIAN_POINT('',(-48.8569340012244,22.0000000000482,-23.));
#1068=VERTEX_POINT('',#1067);
#1069=EDGE_CURVE('E598',#804,#1068,#1066,.T.);
#1070=ORIENTED_EDGE('',*,*,#1069,.T.);
#1071=DIRECTION('',(0.,1.,0.));
#1072=VECTOR('',#1071,1.);
#1073=CARTESIAN_POINT('',(-48.8569340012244,-999932.,-23.));
#1074=LINE('',#1073,#1072);
#1075=EDGE_CURVE('E473',#1068,#273,#1074,.T.);
#1076=ORIENTED_EDGE('',*,*,#1075,.T.);
#1077=ORIENTED_EDGE('',*,*,#298,.F.);
#1078=ORIENTED_EDGE('',*,*,#736,.F.);
#1079=ORIENTED_EDGE('',*,*,#700,.F.);
#1080=DIRECTION('',(0.,-1.,0.));
#1081=VECTOR('',#1080,1.);
#1082=CARTESIAN_POINT('',(-26.,47.9999999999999,-23.));
#1083=LINE('',#1082,#1081);
#1084=EDGE_CURVE('E787',#691,#964,#1083,.T.);
#1085=ORIENTED_EDGE('',*,*,#1084,.T.);
#1086=EDGE_LOOP('',(#968,#974,#975,#976,#977,#985,#1022,#1023,#1024,#1025,#1026,#1027,#1070,
#1076,#1077,#1078,#1079,#1085));
#1087=FACE_BOUND('',#1086,.T.);
#1088=ADVANCED_FACE('F612',(#1087),#957,.F.);
#1089=CARTESIAN_POINT('',(0.,-999932.,0.));
#1090=DIRECTION('',(0.,1.,0.));
#1091=DIRECTION('',(0.,0.,1.));
#1092=AXIS2_PLACEMENT_3D('',#1089,#1090,#1091);
#1093=CYLINDRICAL_SURFACE('',#1092,54.);
#1094=ORIENTED_EDGE('',*,*,#946,.F.);
#1095=CARTESIAN_POINT('',(0.,22.0000000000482,0.));
#1096=DIRECTION('',(0.,-1.,0.));
#1097=DIRECTION('',(1.,0.,0.));
#1098=AXIS2_PLACEMENT_3D('',#1095,#1096,#1097);
#1099=CIRCLE('',#1098,54.);
#1100=EDGE_CURVE('E586',#939,#983,#1099,.F.);
#1101=ORIENTED_EDGE('',*,*,#1100,.T.);
#1102=ORIENTED_EDGE('',*,*,#984,.T.);
#1103=ORIENTED_EDGE('',*,*,#224,.F.);
#1104=EDGE_LOOP('',(#1094,#1101,#1102,#1103));
#1105=FACE_BOUND('',#1104,.T.);
#1106=ADVANCED_FACE('F725',(#1105),#1093,.T.);
#1107=CARTESIAN_POINT('',(0.,-999932.,0.));
#1108=DIRECTION('',(0.,1.,0.));
#1109=DIRECTION('',(0.,0.,1.));
#1110=AXIS2_PLACEMENT_3D('',#1107,#1108,#1109);
#1111=CYLINDRICAL_SURFACE('',#1110,54.);
#1112=ORIENTED_EDGE('',*,*,#1075,.F.);
#1113=CARTESIAN_POINT('',(0.,22.0000000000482,0.));
#1114=DIRECTION('',(0.,-1.,0.));
#1115=DIRECTION('',(1.,0.,0.));
#1116=AXIS2_PLACEMENT_3D('',#1113,#1114,#1115);
#1117=CIRCLE('',#1116,54.);
#1118=EDGE_CURVE('E581',#1068,#854,#1117,.F.);
#1119=ORIENTED_EDGE('',*,*,#1118,.T.);
#1120=ORIENTED_EDGE('',*,*,#855,.T.);
#1121=ORIENTED_EDGE('',*,*,#276,.F.);
#1122=EDGE_LOOP('',(#1112,#1119,#1120,#1121));
#1123=FACE_BOUND('',#1122,.T.);
#1124=ADVANCED_FACE('F723',(#1123),#1111,.T.);
#1125=CARTESIAN_POINT('',(-97.5,2.,17.5));
#1126=DIRECTION('',(-1.,0.,0.));
#1127=DIRECTION('',(0.,0.,1.));
#1128=AXIS2_PLACEMENT_3D('',#1125,#1126,#1127);
#1129=PLANE('',#1128);
#1130=ORIENTED_EDGE('',*,*,#364,.T.);
#1131=DIRECTION('',(0.,-1.,0.));
#1132=VECTOR('',#1131,1.);
#1133=CARTESIAN_POINT('',(-97.5,2.,-17.5));
#1134=LINE('',#1133,#1132);
#1135=EDGE_CURVE('E470',#103,#353,#1134,.T.);
#1136=ORIENTED_EDGE('',*,*,#1135,.F.);
#1137=ORIENTED_EDGE('',*,*,#104,.F.);
#1138=DIRECTION('',(0.,-1.,0.));
#1139=VECTOR('',#1138,1.);
#1140=CARTESIAN_POINT('',(-97.5,2.,17.5));
#1141=LINE('',#1140,#1139);
#1142=EDGE_CURVE('E471',#101,#363,#1141,.T.);
#1143=ORIENTED_EDGE('',*,*,#1142,.T.);
#1144=EDGE_LOOP('',(#1130,#1136,#1137,#1143));
#1145=FACE_BOUND('',#1144,.T.);
#1146=ADVANCED_FACE('F712',(#1145),#1129,.F.);
#1147=CARTESIAN_POINT('',(-97.5,2.,17.5));
#1148=DIRECTION('',(0.,0.,1.));
#1149=DIRECTION('',(1.,0.,0.));
#1150=AXIS2_PLACEMENT_3D('',#1147,#1148,#1149);
#1151=PLANE('',#1150);
#1152=ORIENTED_EDGE('',*,*,#372,.T.);
#1153=ORIENTED_EDGE('',*,*,#1142,.F.);
#1154=ORIENTED_EDGE('',*,*,#126,.F.);
#1155=DIRECTION('',(0.,-1.,0.));
#1156=VECTOR('',#1155,1.);
#1157=CARTESIAN_POINT('',(97.5,2.,17.5));
#1158=LINE('',#1157,#1156);
#1159=EDGE_CURVE('E474',#119,#371,#1158,.T.);
#1160=ORIENTED_EDGE('',*,*,#1159,.T.);
#1161=EDGE_LOOP('',(#1152,#1153,#1154,#1160));
#1162=FACE_BOUND('',#1161,.T.);
#1163=ADVANCED_FACE('F708',(#1162),#1151,.F.);
#1164=CARTESIAN_POINT('',(97.5,2.,17.5));
#1165=DIRECTION('',(1.,0.,0.));
#1166=DIRECTION('',(0.,0.,-1.));
#1167=AXIS2_PLACEMENT_3D('',#1164,#1165,#1166);
#1168=PLANE('',#1167);
#1169=ORIENTED_EDGE('',*,*,#378,.T.);
#1170=ORIENTED_EDGE('',*,*,#1159,.F.);
#1171=ORIENTED_EDGE('',*,*,#120,.F.);
#1172=DIRECTION('',(0.,-1.,0.));
#1173=VECTOR('',#1172,1.);
#1174=CARTESIAN_POINT('',(97.5,2.,-17.5));
#1175=LINE('',#1174,#1173);
#1176=EDGE_CURVE('E476',#111,#355,#1175,.T.);
#1177=ORIENTED_EDGE('',*,*,#1176,.T.);
#1178=EDGE_LOOP('',(#1169,#1170,#1171,#1177));
#1179=FACE_BOUND('',#1178,.T.);
#1180=ADVANCED_FACE('F711',(#1179),#1168,.F.);
#1181=CARTESIAN_POINT('',(-97.5,2.,-17.5));
#1182=DIRECTION('',(0.,0.,-1.));
#1183=DIRECTION('',(-1.,0.,0.));
#1184=AXIS2_PLACEMENT_3D('',#1181,#1182,#1183);
#1185=PLANE('',#1184);
#1186=ORIENTED_EDGE('',*,*,#356,.T.);
#1187=ORIENTED_EDGE('',*,*,#1176,.F.);
#1188=ORIENTED_EDGE('',*,*,#112,.F.);
#1189=ORIENTED_EDGE('',*,*,#1135,.T.);
#1190=EDGE_LOOP('',(#1186,#1187,#1188,#1189));
#1191=FACE_BOUND('',#1190,.T.);
#1192=ADVANCED_FACE('F716',(#1191),#1185,.F.);
#1193=CARTESIAN_POINT('',(26.,12.,13.));
#1194=DIRECTION('',(-1.,0.,0.));
#1195=DIRECTION('',(0.,0.,1.));
#1196=AXIS2_PLACEMENT_3D('',#1193,#1194,#1195);
#1197=PLANE('',#1196);
#1198=ORIENTED_EDGE('',*,*,#138,.T.);
#1199=DIRECTION('',(0.,-1.,0.));
#1200=VECTOR('',#1199,1.);
#1201=CARTESIAN_POINT('',(26.,12.,-13.));
#1202=LINE('',#1201,#1200);
#1203=CARTESIAN_POINT('',(26.,12.,-13.));
#1204=VERTEX_POINT('',#1203);
#1205=EDGE_CURVE('E438',#1204,#137,#1202,.T.);
#1206=ORIENTED_EDGE('',*,*,#1205,.F.);
#1207=DIRECTION('',(0.,0.,-1.));
#1208=VECTOR('',#1207,1.);
#1209=CARTESIAN_POINT('',(26.,12.,13.));
#1210=LINE('',#1209,#1208);
#1211=CARTESIAN_POINT('',(26.,12.,13.));
#1212=VERTEX_POINT('',#1211);
#1213=EDGE_CURVE('E428',#1212,#1204,#1210,.T.);
#1214=ORIENTED_EDGE('',*,*,#1213,.F.);
#1215=DIRECTION('',(0.,-1.,0.));
#1216=VECTOR('',#1215,1.);
#1217=CARTESIAN_POINT('',(26.,12.,13.));
#1218=LINE('',#1217,#1216);
#1219=EDGE_CURVE('E439',#1212,#135,#1218,.T.);
#1220=ORIENTED_EDGE('',*,*,#1219,.T.);
#1221=EDGE_LOOP('',(#1198,#1206,#1214,#1220));
#1222=FACE_BOUND('',#1221,.T.);
#1223=ADVANCED_FACE('F706',(#1222),#1197,.F.);
#1224=CARTESIAN_POINT('',(26.,12.,13.));
#1225=DIRECTION('',(0.,0.,-1.));
#1226=DIRECTION('',(-1.,0.,0.));
#1227=AXIS2_PLACEMENT_3D('',#1224,#1225,#1226);
#1228=PLANE('',#1227);
#1229=ORIENTED_EDGE('',*,*,#146,.F.);
#1230=ORIENTED_EDGE('',*,*,#1219,.F.);
#1231=DIRECTION('',(1.,0.,0.));
#1232=VECTOR('',#1231,1.);
#1233=CARTESIAN_POINT('',(26.,12.,13.));
#1234=LINE('',#1233,#1232);
#1235=CARTESIAN_POINT('',(52.,12.,13.));
#1236=VERTEX_POINT('',#1235);
#1237=EDGE_CURVE('E436',#1212,#1236,#1234,.T.);
#1238=ORIENTED_EDGE('',*,*,#1237,.T.);
#1239=DIRECTION('',(0.,-1.,0.));
#1240=VECTOR('',#1239,1.);
#1241=CARTESIAN_POINT('',(52.,12.,13.));
#1242=LINE('',#1241,#1240);
#1243=EDGE_CURVE('E442',#1236,#145,#1242,.T.);
#1244=ORIENTED_EDGE('',*,*,#1243,.T.);
#1245=EDGE_LOOP('',(#1229,#1230,#1238,#1244));
#1246=FACE_BOUND('',#1245,.T.);
#1247=ADVANCED_FACE('F989',(#1246),#1228,.T.);
#1248=CARTESIAN_POINT('',(52.,12.,13.));
#1249=DIRECTION('',(-1.,0.,0.));
#1250=DIRECTION('',(0.,0.,1.));
#1251=AXIS2_PLACEMENT_3D('',#1248,#1249,#1250);
#1252=PLANE('',#1251);
#1253=ORIENTED_EDGE('',*,*,#154,.F.);
#1254=ORIENTED_EDGE('',*,*,#1243,.F.);
#1255=DIRECTION('',(0.,0.,-1.));
#1256=VECTOR('',#1255,1.);
#1257=CARTESIAN_POINT('',(52.,12.,13.));
#1258=LINE('',#1257,#1256);
#1259=CARTESIAN_POINT('',(52.,12.,-13.));
#1260=VERTEX_POINT('',#1259);
#1261=EDGE_CURVE('E434',#1236,#1260,#1258,.T.);
#1262=ORIENTED_EDGE('',*,*,#1261,.T.);
#1263=DIRECTION('',(0.,-1.,0.));
#1264=VECTOR('',#1263,1.);
#1265=CARTESIAN_POINT('',(52.,12.,-13.));
#1266=LINE('',#1265,#1264);
#1267=EDGE_CURVE('E444',#1260,#153,#1266,.T.);
#1268=ORIENTED_EDGE('',*,*,#1267,.T.);
#1269=EDGE_LOOP('',(#1253,#1254,#1262,#1268));
#1270=FACE_BOUND('',#1269,.T.);
#1271=ADVANCED_FACE('F992',(#1270),#1252,.T.);
#1272=CARTESIAN_POINT('',(26.,12.,-13.));
#1273=DIRECTION('',(0.,0.,-1.));
#1274=DIRECTION('',(-1.,0.,0.));
#1275=AXIS2_PLACEMENT_3D('',#1272,#1273,#1274);
#1276=PLANE('',#1275);
#1277=ORIENTED_EDGE('',*,*,#160,.T.);
#1278=ORIENTED_EDGE('',*,*,#1267,.F.);
#1279=DIRECTION('',(1.,0.,0.));
#1280=VECTOR('',#1279,1.);
#1281=CARTESIAN_POINT('',(26.,12.,-13.));
#1282=LINE('',#1281,#1280);
#1283=EDGE_CURVE('E431',#1204,#1260,#1282,.T.);
#1284=ORIENTED_EDGE('',*,*,#1283,.F.);
#1285=ORIENTED_EDGE('',*,*,#1205,.T.);
#1286=EDGE_LOOP('',(#1277,#1278,#1284,#1285));
#1287=FACE_BOUND('',#1286,.T.);
#1288=ADVANCED_FACE('F987',(#1287),#1276,.F.);
#1289=CARTESIAN_POINT('',(26.,12.,-13.));
#1290=DIRECTION('',(0.,-1.,0.));
#1291=DIRECTION('',(0.,0.,-1.));
#1292=AXIS2_PLACEMENT_3D('',#1289,#1290,#1291);
#1293=PLANE('',#1292);
#1294=CARTESIAN_POINT('',(39.,12.,0.));
#1295=DIRECTION('',(0.,-1.,0.));
#1296=DIRECTION('',(0.,0.,-1.));
#1297=AXIS2_PLACEMENT_3D('',#1294,#1295,#1296);
#1298=CIRCLE('',#1297,6.);
#1299=CARTESIAN_POINT('',(39.,12.,-6.));
#1300=VERTEX_POINT('',#1299);
#1301=EDGE_CURVE('E372',#1300,#1300,#1298,.T.);
#1302=ORIENTED_EDGE('',*,*,#1301,.F.);
#1303=EDGE_LOOP('',(#1302));
#1304=FACE_BOUND('',#1303,.T.);
#1305=ORIENTED_EDGE('',*,*,#1213,.T.);
#1306=ORIENTED_EDGE('',*,*,#1283,.T.);
#1307=ORIENTED_EDGE('',*,*,#1261,.F.);
#1308=ORIENTED_EDGE('',*,*,#1237,.F.);
#1309=EDGE_LOOP('',(#1305,#1306,#1307,#1308));
#1310=FACE_BOUND('',#1309,.T.);
#1311=ADVANCED_FACE('F969',(#1304,#1310),#1293,.T.);
#1312=CARTESIAN_POINT('',(-26.,12.,13.));
#1313=DIRECTION('',(-1.,0.,0.));
#1314=DIRECTION('',(0.,0.,1.));
#1315=AXIS2_PLACEMENT_3D('',#1312,#1313,#1314);
#1316=PLANE('',#1315);
#1317=ORIENTED_EDGE('',*,*,#180,.F.);
#1318=DIRECTION('',(0.,-1.,0.));
#1319=VECTOR('',#1318,1.);
#1320=CARTESIAN_POINT('',(-26.,12.,13.));
#1321=LINE('',#1320,#1319);
#1322=CARTESIAN_POINT('',(-26.,12.,13.));
#1323=VERTEX_POINT('',#1322);
#1324=EDGE_CURVE('E391',#1323,#169,#1321,.T.);
#1325=ORIENTED_EDGE('',*,*,#1324,.F.);
#1326=DIRECTION('',(0.,0.,-1.));
#1327=VECTOR('',#1326,1.);
#1328=CARTESIAN_POINT('',(-26.,12.,13.));
#1329=LINE('',#1328,#1327);
#1330=CARTESIAN_POINT('',(-26.,12.,-13.));
#1331=VERTEX_POINT('',#1330);
#1332=EDGE_CURVE('E402',#1323,#1331,#1329,.T.);
#1333=ORIENTED_EDGE('',*,*,#1332,.T.);
#1334=DIRECTION('',(0.,-1.,0.));
#1335=VECTOR('',#1334,1.);
#1336=CARTESIAN_POINT('',(-26.,12.,-13.));
#1337=LINE('',#1336,#1335);
#1338=EDGE_CURVE('E384',#1331,#179,#1337,.T.);
#1339=ORIENTED_EDGE('',*,*,#1338,.T.);
#1340=EDGE_LOOP('',(#1317,#1325,#1333,#1339));
#1341=FACE_BOUND('',#1340,.T.);
#1342=ADVANCED_FACE('F965',(#1341),#1316,.T.);
#1343=CARTESIAN_POINT('',(-26.,12.,-13.));
#1344=DIRECTION('',(0.,0.,1.));
#1345=DIRECTION('',(1.,0.,0.));
#1346=AXIS2_PLACEMENT_3D('',#1343,#1344,#1345);
#1347=PLANE('',#1346);
#1348=ORIENTED_EDGE('',*,*,#188,.F.);
#1349=ORIENTED_EDGE('',*,*,#1338,.F.);
#1350=DIRECTION('',(-1.,0.,0.));
#1351=VECTOR('',#1350,1.);
#1352=CARTESIAN_POINT('',(-26.,12.,-13.));
#1353=LINE('',#1352,#1351);
#1354=CARTESIAN_POINT('',(-52.,12.,-13.));
#1355=VERTEX_POINT('',#1354);
#1356=EDGE_CURVE('E400',#1331,#1355,#1353,.T.);
#1357=ORIENTED_EDGE('',*,*,#1356,.T.);
#1358=DIRECTION('',(0.,-1.,0.));
#1359=VECTOR('',#1358,1.);
#1360=CARTESIAN_POINT('',(-52.,12.,-13.));
#1361=LINE('',#1360,#1359);
#1362=EDGE_CURVE('E387',#1355,#187,#1361,.T.);
#1363=ORIENTED_EDGE('',*,*,#1362,.T.);
#1364=EDGE_LOOP('',(#1348,#1349,#1357,#1363));
#1365=FACE_BOUND('',#1364,.T.);
#1366=ADVANCED_FACE('F968',(#1365),#1347,.T.);
#1367=CARTESIAN_POINT('',(-52.,12.,13.));
#1368=DIRECTION('',(-1.,0.,0.));
#1369=DIRECTION('',(0.,0.,1.));
#1370=AXIS2_PLACEMENT_3D('',#1367,#1368,#1369);
#1371=PLANE('',#1370);
#1372=ORIENTED_EDGE('',*,*,#194,.T.);
#1373=ORIENTED_EDGE('',*,*,#1362,.F.);
#1374=DIRECTION('',(0.,0.,-1.));
#1375=VECTOR('',#1374,1.);
#1376=CARTESIAN_POINT('',(-52.,12.,13.));
#1377=LINE('',#1376,#1375);
#1378=CARTESIAN_POINT('',(-52.,12.,13.));
#1379=VERTEX_POINT('',#1378);
#1380=EDGE_CURVE('E397',#1379,#1355,#1377,.T.);
#1381=ORIENTED_EDGE('',*,*,#1380,.F.);
#1382=DIRECTION('',(0.,-1.,0.));
#1383=VECTOR('',#1382,1.);
#1384=CARTESIAN_POINT('',(-52.,12.,13.));
#1385=LINE('',#1384,#1383);
#1386=EDGE_CURVE('E389',#1379,#171,#1385,.T.);
#1387=ORIENTED_EDGE('',*,*,#1386,.T.);
#1388=EDGE_LOOP('',(#1372,#1373,#1381,#1387));
#1389=FACE_BOUND('',#1388,.T.);
#1390=ADVANCED_FACE('F973',(#1389),#1371,.F.);
#1391=CARTESIAN_POINT('',(-26.,12.,13.));
#1392=DIRECTION('',(0.,0.,1.));
#1393=DIRECTION('',(1.,0.,0.));
#1394=AXIS2_PLACEMENT_3D('',#1391,#1392,#1393);
#1395=PLANE('',#1394);
#1396=ORIENTED_EDGE('',*,*,#172,.T.);
#1397=ORIENTED_EDGE('',*,*,#1386,.F.);
#1398=DIRECTION('',(-1.,0.,0.));
#1399=VECTOR('',#1398,1.);
#1400=CARTESIAN_POINT('',(-26.,12.,13.));
#1401=LINE('',#1400,#1399);
#1402=EDGE_CURVE('E394',#1323,#1379,#1401,.T.);
#1403=ORIENTED_EDGE('',*,*,#1402,.F.);
#1404=ORIENTED_EDGE('',*,*,#1324,.T.);
#1405=EDGE_LOOP('',(#1396,#1397,#1403,#1404));
#1406=FACE_BOUND('',#1405,.T.);
#1407=ADVANCED_FACE('F977',(#1406),#1395,.F.);
#1408=CARTESIAN_POINT('',(-26.,12.,-13.));
#1409=DIRECTION('',(0.,1.,0.));
#1410=DIRECTION('',(0.,0.,1.));
#1411=AXIS2_PLACEMENT_3D('',#1408,#1409,#1410);
#1412=PLANE('',#1411);
#1413=CARTESIAN_POINT('',(-39.,12.,0.));
#1414=DIRECTION('',(0.,-1.,0.));
#1415=DIRECTION('',(0.,0.,-1.));
#1416=AXIS2_PLACEMENT_3D('',#1413,#1414,#1415);
#1417=CIRCLE('',#1416,6.);
#1418=CARTESIAN_POINT('',(-39.,12.,-6.00000000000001));
#1419=VERTEX_POINT('',#1418);
#1420=EDGE_CURVE('E378',#1419,#1419,#1417,.T.);
#1421=ORIENTED_EDGE('',*,*,#1420,.F.);
#1422=EDGE_LOOP('',(#1421));
#1423=FACE_BOUND('',#1422,.T.);
#1424=ORIENTED_EDGE('',*,*,#1332,.F.);
#1425=ORIENTED_EDGE('',*,*,#1402,.T.);
#1426=ORIENTED_EDGE('',*,*,#1380,.T.);
#1427=ORIENTED_EDGE('',*,*,#1356,.F.);
#1428=EDGE_LOOP('',(#1424,#1425,#1426,#1427));
#1429=FACE_BOUND('',#1428,.T.);
#1430=ADVANCED_FACE('F963',(#1423,#1429),#1412,.F.);
#1431=CARTESIAN_POINT('',(-39.,68.,0.));
#1432=DIRECTION('',(0.,-1.,0.));
#1433=DIRECTION('',(0.,0.,-1.));
#1434=AXIS2_PLACEMENT_3D('',#1431,#1432,#1433);
#1435=CYLINDRICAL_SURFACE('',#1434,6.);
#1436=ORIENTED_EDGE('',*,*,#263,.F.);
#1437=EDGE_LOOP('',(#1436));
#1438=FACE_BOUND('',#1437,.T.);
#1439=ORIENTED_EDGE('',*,*,#1420,.T.);
#1440=EDGE_LOOP('',(#1439));
#1441=FACE_BOUND('',#1440,.T.);
#1442=ADVANCED_FACE('F959',(#1438,#1441),#1435,.F.);
#1443=CARTESIAN_POINT('',(39.,68.,0.));
#1444=DIRECTION('',(0.,-1.,0.));
#1445=DIRECTION('',(0.,0.,-1.));
#1446=AXIS2_PLACEMENT_3D('',#1443,#1444,#1445);
#1447=CYLINDRICAL_SURFACE('',#1446,6.);
#1448=ORIENTED_EDGE('',*,*,#211,.F.);
#1449=EDGE_LOOP('',(#1448));
#1450=FACE_BOUND('',#1449,.T.);
#1451=ORIENTED_EDGE('',*,*,#1301,.T.);
#1452=EDGE_LOOP('',(#1451));
#1453=FACE_BOUND('',#1452,.T.);
#1454=ADVANCED_FACE('F951',(#1450,#1453),#1447,.F.);
#1455=CARTESIAN_POINT('',(-77.,0.,0.));
#1456=DIRECTION('',(0.,1.,0.));
#1457=DIRECTION('',(-1.,0.,0.));
#1458=AXIS2_PLACEMENT_3D('',#1455,#1456,#1457);
#1459=CYLINDRICAL_SURFACE('',#1458,6.);
#1460=DIRECTION('',(0.,1.,0.));
#1461=VECTOR('',#1460,1.);
#1462=CARTESIAN_POINT('',(-77.,0.,6.));
#1463=LINE('',#1462,#1461);
#1464=CARTESIAN_POINT('',(-77.,13.,6.));
#1465=VERTEX_POINT('',#1464);
#1466=EDGE_CURVE('E355',#68,#1465,#1463,.T.);
#1467=ORIENTED_EDGE('',*,*,#1466,.T.);
#1468=CARTESIAN_POINT('',(-77.,13.,0.));
#1469=DIRECTION('',(0.,-1.,0.));
#1470=DIRECTION('',(0.,0.,-1.));
#1471=AXIS2_PLACEMENT_3D('',#1468,#1469,#1470);
#1472=CIRCLE('',#1471,6.);
#1473=CARTESIAN_POINT('',(-77.,13.,-6.));
#1474=VERTEX_POINT('',#1473);
#1475=EDGE_CURVE('E903',#1465,#1474,#1472,.F.);
#1476=ORIENTED_EDGE('',*,*,#1475,.T.);
#1477=DIRECTION('',(0.,1.,0.));
#1478=VECTOR('',#1477,1.);
#1479=CARTESIAN_POINT('',(-77.,0.,-6.));
#1480=LINE('',#1479,#1478);
#1481=EDGE_CURVE('E347',#66,#1474,#1480,.T.);
#1482=ORIENTED_EDGE('',*,*,#1481,.F.);
#1483=ORIENTED_EDGE('',*,*,#69,.T.);
#1484=EDGE_LOOP('',(#1467,#1476,#1482,#1483));
#1485=FACE_BOUND('',#1484,.T.);
#1486=ADVANCED_FACE('F933',(#1485),#1459,.F.);
#1487=CARTESIAN_POINT('',(-77.,0.,6.));
#1488=DIRECTION('',(0.,0.,1.));
#1489=DIRECTION('',(1.,0.,0.));
#1490=AXIS2_PLACEMENT_3D('',#1487,#1488,#1489);
#1491=PLANE('',#1490);
#1492=DIRECTION('',(0.,1.,0.));
#1493=VECTOR('',#1492,1.);
#1494=CARTESIAN_POINT('',(-85.,0.,5.99999999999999));
#1495=LINE('',#1494,#1493);
#1496=CARTESIAN_POINT('',(-85.,13.,5.99999999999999));
#1497=VERTEX_POINT('',#1496);
#1498=EDGE_CURVE('E359',#85,#1497,#1495,.T.);
#1499=ORIENTED_EDGE('',*,*,#1498,.T.);
#1500=DIRECTION('',(1.,0.,0.));
#1501=VECTOR('',#1500,1.);
#1502=CARTESIAN_POINT('',(-77.,13.,6.));
#1503=LINE('',#1502,#1501);
#1504=EDGE_CURVE('E901',#1497,#1465,#1503,.T.);
#1505=ORIENTED_EDGE('',*,*,#1504,.T.);
#1506=ORIENTED_EDGE('',*,*,#1466,.F.);
#1507=ORIENTED_EDGE('',*,*,#92,.T.);
#1508=EDGE_LOOP('',(#1499,#1505,#1506,#1507));
#1509=FACE_BOUND('',#1508,.T.);
#1510=ADVANCED_FACE('F943',(#1509),#1491,.F.);
#1511=CARTESIAN_POINT('',(-85.,0.,0.));
#1512=DIRECTION('',(0.,1.,0.));
#1513=DIRECTION('',(-1.,0.,0.));
#1514=AXIS2_PLACEMENT_3D('',#1511,#1512,#1513);
#1515=CYLINDRICAL_SURFACE('',#1514,6.);
#1516=DIRECTION('',(0.,1.,0.));
#1517=VECTOR('',#1516,1.);
#1518=CARTESIAN_POINT('',(-85.,0.,-6.00000000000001));
#1519=LINE('',#1518,#1517);
#1520=CARTESIAN_POINT('',(-85.,13.,-6.00000000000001));
#1521=VERTEX_POINT('',#1520);
#1522=EDGE_CURVE('E350',#76,#1521,#1519,.T.);
#1523=ORIENTED_EDGE('',*,*,#1522,.T.);
#1524=CARTESIAN_POINT('',(-85.,13.,0.));
#1525=DIRECTION('',(0.,-1.,0.));
#1526=DIRECTION('',(0.,0.,-1.));
#1527=AXIS2_PLACEMENT_3D('',#1524,#1525,#1526);
#1528=CIRCLE('',#1527,6.);
#1529=EDGE_CURVE('E905',#1521,#1497,#1528,.F.);
#1530=ORIENTED_EDGE('',*,*,#1529,.T.);
#1531=ORIENTED_EDGE('',*,*,#1498,.F.);
#1532=ORIENTED_EDGE('',*,*,#86,.T.);
#1533=EDGE_LOOP('',(#1523,#1530,#1531,#1532));
#1534=FACE_BOUND('',#1533,.T.);
#1535=ADVANCED_FACE('F924',(#1534),#1515,.F.);
#1536=CARTESIAN_POINT('',(-77.,0.,-6.));
#1537=DIRECTION('',(0.,0.,-1.));
#1538=DIRECTION('',(-1.,0.,0.));
#1539=AXIS2_PLACEMENT_3D('',#1536,#1537,#1538);
#1540=PLANE('',#1539);
#1541=ORIENTED_EDGE('',*,*,#1481,.T.);
#1542=DIRECTION('',(-1.,0.,0.));
#1543=VECTOR('',#1542,1.);
#1544=CARTESIAN_POINT('',(-77.,13.,-6.));
#1545=LINE('',#1544,#1543);
#1546=EDGE_CURVE('E624',#1474,#1521,#1545,.T.);
#1547=ORIENTED_EDGE('',*,*,#1546,.T.);
#1548=ORIENTED_EDGE('',*,*,#1522,.F.);
#1549=ORIENTED_EDGE('',*,*,#77,.T.);
#1550=EDGE_LOOP('',(#1541,#1547,#1548,#1549));
#1551=FACE_BOUND('',#1550,.T.);
#1552=ADVANCED_FACE('F920',(#1551),#1540,.F.);
#1553=CARTESIAN_POINT('',(85.,0.,0.));
#1554=DIRECTION('',(0.,1.,0.));
#1555=DIRECTION('',(-1.,0.,0.));
#1556=AXIS2_PLACEMENT_3D('',#1553,#1554,#1555);
#1557=CYLINDRICAL_SURFACE('',#1556,6.);
#1558=DIRECTION('',(0.,1.,0.));
#1559=VECTOR('',#1558,1.);
#1560=CARTESIAN_POINT('',(85.,0.,5.99999999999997));
#1561=LINE('',#1560,#1559);
#1562=CARTESIAN_POINT('',(85.,13.,5.99999999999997));
#1563=VERTEX_POINT('',#1562);
#1564=EDGE_CURVE('E333',#32,#1563,#1561,.T.);
#1565=ORIENTED_EDGE('',*,*,#1564,.T.);
#1566=CARTESIAN_POINT('',(85.,13.,0.));
#1567=DIRECTION('',(0.,-1.,0.));
#1568=DIRECTION('',(0.,0.,-1.));
#1569=AXIS2_PLACEMENT_3D('',#1566,#1567,#1568);
#1570=CIRCLE('',#1569,6.);
#1571=CARTESIAN_POINT('',(85.,13.,-6.00000000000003));
#1572=VERTEX_POINT('',#1571);
#1573=EDGE_CURVE('E341',#1563,#1572,#1570,.F.);
#1574=ORIENTED_EDGE('',*,*,#1573,.T.);
#1575=DIRECTION('',(0.,1.,0.));
#1576=VECTOR('',#1575,1.);
#1577=CARTESIAN_POINT('',(85.,0.,-6.00000000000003));
#1578=LINE('',#1577,#1576);
#1579=EDGE_CURVE('E324',#30,#1572,#1578,.T.);
#1580=ORIENTED_EDGE('',*,*,#1579,.F.);
#1581=ORIENTED_EDGE('',*,*,#33,.T.);
#1582=EDGE_LOOP('',(#1565,#1574,#1580,#1581));
#1583=FACE_BOUND('',#1582,.T.);
#1584=ADVANCED_FACE('F337',(#1583),#1557,.F.);
#1585=CARTESIAN_POINT('',(77.,0.,5.99999999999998));
#1586=DIRECTION('',(0.,0.,1.));
#1587=DIRECTION('',(1.,0.,0.));
#1588=AXIS2_PLACEMENT_3D('',#1585,#1586,#1587);
#1589=PLANE('',#1588);
#1590=DIRECTION('',(0.,1.,0.));
#1591=VECTOR('',#1590,1.);
#1592=CARTESIAN_POINT('',(77.,0.,6.00000000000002));
#1593=LINE('',#1592,#1591);
#1594=CARTESIAN_POINT('',(77.,13.,6.00000000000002));
#1595=VERTEX_POINT('',#1594);
#1596=EDGE_CURVE('E869',#49,#1595,#1593,.T.);
#1597=ORIENTED_EDGE('',*,*,#1596,.T.);
#1598=DIRECTION('',(1.,0.,0.));
#1599=VECTOR('',#1598,1.);
#1600=CARTESIAN_POINT('',(77.,13.,5.99999999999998));
#1601=LINE('',#1600,#1599);
#1602=EDGE_CURVE('E837',#1595,#1563,#1601,.T.);
#1603=ORIENTED_EDGE('',*,*,#1602,.T.);
#1604=ORIENTED_EDGE('',*,*,#1564,.F.);
#1605=ORIENTED_EDGE('',*,*,#56,.T.);
#1606=EDGE_LOOP('',(#1597,#1603,#1604,#1605));
#1607=FACE_BOUND('',#1606,.T.);
#1608=ADVANCED_FACE('F879',(#1607),#1589,.F.);
#1609=CARTESIAN_POINT('',(77.,0.,0.));
#1610=DIRECTION('',(0.,1.,0.));
#1611=DIRECTION('',(-1.,0.,0.));
#1612=AXIS2_PLACEMENT_3D('',#1609,#1610,#1611);
#1613=CYLINDRICAL_SURFACE('',#1612,6.);
#1614=DIRECTION('',(0.,1.,0.));
#1615=VECTOR('',#1614,1.);
#1616=CARTESIAN_POINT('',(77.,0.,-6.00000000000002));
#1617=LINE('',#1616,#1615);
#1618=CARTESIAN_POINT('',(77.,13.,-6.00000000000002));
#1619=VERTEX_POINT('',#1618);
#1620=EDGE_CURVE('E327',#40,#1619,#1617,.T.);
#1621=ORIENTED_EDGE('',*,*,#1620,.T.);
#1622=CARTESIAN_POINT('',(77.,13.,0.));
#1623=DIRECTION('',(0.,-1.,0.));
#1624=DIRECTION('',(0.,0.,-1.));
#1625=AXIS2_PLACEMENT_3D('',#1622,#1623,#1624);
#1626=CIRCLE('',#1625,6.);
#1627=EDGE_CURVE('E876',#1619,#1595,#1626,.F.);
#1628=ORIENTED_EDGE('',*,*,#1627,.T.);
#1629=ORIENTED_EDGE('',*,*,#1596,.F.);
#1630=ORIENTED_EDGE('',*,*,#50,.T.);
#1631=EDGE_LOOP('',(#1621,#1628,#1629,#1630));
#1632=FACE_BOUND('',#1631,.T.);
#1633=ADVANCED_FACE('F874',(#1632),#1613,.F.);
#1634=CARTESIAN_POINT('',(77.,0.,-6.00000000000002));
#1635=DIRECTION('',(0.,0.,-1.));
#1636=DIRECTION('',(-1.,0.,0.));
#1637=AXIS2_PLACEMENT_3D('',#1634,#1635,#1636);
#1638=PLANE('',#1637);
#1639=ORIENTED_EDGE('',*,*,#1579,.T.);
#1640=DIRECTION('',(-1.,0.,0.));
#1641=VECTOR('',#1640,1.);
#1642=CARTESIAN_POINT('',(77.,13.,-6.00000000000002));
#1643=LINE('',#1642,#1641);
#1644=EDGE_CURVE('E899',#1572,#1619,#1643,.T.);
#1645=ORIENTED_EDGE('',*,*,#1644,.T.);
#1646=ORIENTED_EDGE('',*,*,#1620,.F.);
#1647=ORIENTED_EDGE('',*,*,#41,.T.);
#1648=EDGE_LOOP('',(#1639,#1645,#1646,#1647));
#1649=FACE_BOUND('',#1648,.T.);
#1650=ADVANCED_FACE('F322',(#1649),#1638,.F.);
#1651=CARTESIAN_POINT('',(0.,22.0000000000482,0.));
#1652=DIRECTION('',(0.,-1.,0.));
#1653=DIRECTION('',(1.,0.,0.));
#1654=AXIS2_PLACEMENT_3D('',#1651,#1652,#1653);
#1655=TOROIDAL_SURFACE('',#1654,62.,8.);
#1656=ORIENTED_EDGE('',*,*,#1069,.F.);
#1657=ORIENTED_EDGE('',*,*,#805,.F.);
#1658=ORIENTED_EDGE('',*,*,#892,.F.);
#1659=ORIENTED_EDGE('',*,*,#1118,.F.);
#1660=EDGE_LOOP('',(#1656,#1657,#1658,#1659));
#1661=FACE_BOUND('',#1660,.T.);
#1662=ADVANCED_FACE('F604',(#1661),#1655,.F.);
#1663=CARTESIAN_POINT('',(0.,22.0000000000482,0.));
#1664=DIRECTION('',(0.,-1.,0.));
#1665=DIRECTION('',(1.,0.,0.));
#1666=AXIS2_PLACEMENT_3D('',#1663,#1664,#1665);
#1667=TOROIDAL_SURFACE('',#1666,62.,8.);
#1668=ORIENTED_EDGE('',*,*,#940,.F.);
#1669=ORIENTED_EDGE('',*,*,#495,.F.);
#1670=ORIENTED_EDGE('',*,*,#1021,.F.);
#1671=ORIENTED_EDGE('',*,*,#1100,.F.);
#1672=EDGE_LOOP('',(#1668,#1669,#1670,#1671));
#1673=FACE_BOUND('',#1672,.T.);
#1674=ADVANCED_FACE('F630',(#1673),#1667,.F.);
#1675=CARTESIAN_POINT('',(-77.,13.,6.));
#1676=DIRECTION('',(0.,-0.707106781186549,0.707106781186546));
#1677=DIRECTION('',(0.,-0.707106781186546,-0.707106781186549));
#1678=AXIS2_PLACEMENT_3D('',#1675,#1676,#1677);
#1679=PLANE('',#1678);
#1680=DIRECTION('',(0.,-0.707106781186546,-0.707106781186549));
#1681=VECTOR('',#1680,1.);
#1682=CARTESIAN_POINT('',(-85.,14.,6.99999999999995));
#1683=LINE('',#1682,#1681);
#1684=EDGE_CURVE('E863',#760,#1497,#1683,.T.);
#1685=ORIENTED_EDGE('',*,*,#1684,.F.);
#1686=ORIENTED_EDGE('',*,*,#786,.F.);
#1687=DIRECTION('',(0.,0.707106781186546,0.707106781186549));
#1688=VECTOR('',#1687,1.);
#1689=CARTESIAN_POINT('',(-77.,13.,6.));
#1690=LINE('',#1689,#1688);
#1691=EDGE_CURVE('E342',#1465,#779,#1690,.T.);
#1692=ORIENTED_EDGE('',*,*,#1691,.F.);
#1693=ORIENTED_EDGE('',*,*,#1504,.F.);
#1694=EDGE_LOOP('',(#1685,#1686,#1692,#1693));
#1695=FACE_BOUND('',#1694,.T.);
#1696=ADVANCED_FACE('F634',(#1695),#1679,.F.);
#1697=CARTESIAN_POINT('',(-77.,13.,0.));
#1698=DIRECTION('',(0.,1.,0.));
#1699=DIRECTION('',(0.,0.,1.));
#1700=AXIS2_PLACEMENT_3D('',#1697,#1698,#1699);
#1701=CONICAL_SURFACE('',#1700,6.,0.78539816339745);
#1702=ORIENTED_EDGE('',*,*,#1691,.T.);
#1703=ORIENTED_EDGE('',*,*,#780,.F.);
#1704=DIRECTION('',(0.,0.707106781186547,-0.707106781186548));
#1705=VECTOR('',#1704,1.);
#1706=CARTESIAN_POINT('',(-77.,13.,-6.));
#1707=LINE('',#1706,#1705);
#1708=EDGE_CURVE('E861',#1474,#770,#1707,.T.);
#1709=ORIENTED_EDGE('',*,*,#1708,.F.);
#1710=ORIENTED_EDGE('',*,*,#1475,.F.);
#1711=EDGE_LOOP('',(#1702,#1703,#1709,#1710));
#1712=FACE_BOUND('',#1711,.T.);
#1713=ADVANCED_FACE('F639',(#1712),#1701,.F.);
#1714=CARTESIAN_POINT('',(-85.,13.,0.));
#1715=DIRECTION('',(0.,1.,0.));
#1716=DIRECTION('',(0.,0.,1.));
#1717=AXIS2_PLACEMENT_3D('',#1714,#1715,#1716);
#1718=CONICAL_SURFACE('',#1717,6.,0.78539816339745);
#1719=ORIENTED_EDGE('',*,*,#1684,.T.);
#1720=ORIENTED_EDGE('',*,*,#1529,.F.);
#1721=DIRECTION('',(0.,-0.707106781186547,0.707106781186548));
#1722=VECTOR('',#1721,1.);
#1723=CARTESIAN_POINT('',(-85.,14.,-6.99999999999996));
#1724=LINE('',#1723,#1722);
#1725=EDGE_CURVE('E859',#762,#1521,#1724,.T.);
#1726=ORIENTED_EDGE('',*,*,#1725,.F.);
#1727=ORIENTED_EDGE('',*,*,#763,.F.);
#1728=EDGE_LOOP('',(#1719,#1720,#1726,#1727));
#1729=FACE_BOUND('',#1728,.T.);
#1730=ADVANCED_FACE('F643',(#1729),#1718,.F.);
#1731=CARTESIAN_POINT('',(-77.,13.,-6.));
#1732=DIRECTION('',(0.,-0.707106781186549,-0.707106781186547));
#1733=DIRECTION('',(0.,0.707106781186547,-0.707106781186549));
#1734=AXIS2_PLACEMENT_3D('',#1731,#1732,#1733);
#1735=PLANE('',#1734);
#1736=ORIENTED_EDGE('',*,*,#1708,.T.);
#1737=ORIENTED_EDGE('',*,*,#771,.F.);
#1738=ORIENTED_EDGE('',*,*,#1725,.T.);
#1739=ORIENTED_EDGE('',*,*,#1546,.F.);
#1740=EDGE_LOOP('',(#1736,#1737,#1738,#1739));
#1741=FACE_BOUND('',#1740,.T.);
#1742=ADVANCED_FACE('F647',(#1741),#1735,.F.);
#1743=CARTESIAN_POINT('',(77.,13.,5.99999999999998));
#1744=DIRECTION('',(0.,-0.707106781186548,0.707106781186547));
#1745=DIRECTION('',(0.,-0.707106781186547,-0.707106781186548));
#1746=AXIS2_PLACEMENT_3D('',#1743,#1744,#1745);
#1747=PLANE('',#1746);
#1748=DIRECTION('',(0.,-0.707106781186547,-0.707106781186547));
#1749=VECTOR('',#1748,1.);
#1750=CARTESIAN_POINT('',(77.,14.,6.99999999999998));
#1751=LINE('',#1750,#1749);
#1752=EDGE_CURVE('E853',#450,#1595,#1751,.T.);
#1753=ORIENTED_EDGE('',*,*,#1752,.F.);
#1754=ORIENTED_EDGE('',*,*,#476,.F.);
#1755=DIRECTION('',(0.,0.707106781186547,0.707106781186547));
#1756=VECTOR('',#1755,1.);
#1757=CARTESIAN_POINT('',(85.,13.,5.99999999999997));
#1758=LINE('',#1757,#1756);
#1759=EDGE_CURVE('E856',#1563,#469,#1758,.T.);
#1760=ORIENTED_EDGE('',*,*,#1759,.F.);
#1761=ORIENTED_EDGE('',*,*,#1602,.F.);
#1762=EDGE_LOOP('',(#1753,#1754,#1760,#1761));
#1763=FACE_BOUND('',#1762,.T.);
#1764=ADVANCED_FACE('F651',(#1763),#1747,.F.);
#1765=CARTESIAN_POINT('',(85.,13.,0.));
#1766=DIRECTION('',(0.,1.,0.));
#1767=DIRECTION('',(0.,0.,1.));
#1768=AXIS2_PLACEMENT_3D('',#1765,#1766,#1767);
#1769=CONICAL_SURFACE('',#1768,6.,0.785398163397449);
#1770=ORIENTED_EDGE('',*,*,#1759,.T.);
#1771=ORIENTED_EDGE('',*,*,#470,.F.);
#1772=DIRECTION('',(0.,0.707106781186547,-0.707106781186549));
#1773=VECTOR('',#1772,1.);
#1774=CARTESIAN_POINT('',(85.,13.,-5.99999999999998));
#1775=LINE('',#1774,#1773);
#1776=EDGE_CURVE('E847',#1572,#460,#1775,.T.);
#1777=ORIENTED_EDGE('',*,*,#1776,.F.);
#1778=ORIENTED_EDGE('',*,*,#1573,.F.);
#1779=EDGE_LOOP('',(#1770,#1771,#1777,#1778));
#1780=FACE_BOUND('',#1779,.T.);
#1781=ADVANCED_FACE('F655',(#1780),#1769,.F.);
#1782=CARTESIAN_POINT('',(77.,13.,0.));
#1783=DIRECTION('',(0.,1.,0.));
#1784=DIRECTION('',(0.,0.,1.));
#1785=AXIS2_PLACEMENT_3D('',#1782,#1783,#1784);
#1786=CONICAL_SURFACE('',#1785,6.,0.785398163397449);
#1787=ORIENTED_EDGE('',*,*,#1752,.T.);
#1788=ORIENTED_EDGE('',*,*,#1627,.F.);
#1789=DIRECTION('',(0.,-0.707106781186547,0.707106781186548));
#1790=VECTOR('',#1789,1.);
#1791=CARTESIAN_POINT('',(77.,14.,-6.99999999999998));
#1792=LINE('',#1791,#1790);
#1793=EDGE_CURVE('E845',#452,#1619,#1792,.T.);
#1794=ORIENTED_EDGE('',*,*,#1793,.F.);
#1795=ORIENTED_EDGE('',*,*,#453,.F.);
#1796=EDGE_LOOP('',(#1787,#1788,#1794,#1795));
#1797=FACE_BOUND('',#1796,.T.);
#1798=ADVANCED_FACE('F659',(#1797),#1786,.F.);
#1799=CARTESIAN_POINT('',(77.,13.,-6.00000000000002));
#1800=DIRECTION('',(0.,-0.707106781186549,-0.707106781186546));
#1801=DIRECTION('',(0.,0.707106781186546,-0.707106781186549));
#1802=AXIS2_PLACEMENT_3D('',#1799,#1800,#1801);
#1803=PLANE('',#1802);
#1804=ORIENTED_EDGE('',*,*,#1776,.T.);
#1805=ORIENTED_EDGE('',*,*,#461,.F.);
#1806=ORIENTED_EDGE('',*,*,#1793,.T.);
#1807=ORIENTED_EDGE('',*,*,#1644,.F.);
#1808=EDGE_LOOP('',(#1804,#1805,#1806,#1807));
#1809=FACE_BOUND('',#1808,.T.);
#1810=ADVANCED_FACE('F663',(#1809),#1803,.F.);
#1811=CARTESIAN_POINT('',(-24.,52.,-21.));
#1812=DIRECTION('',(-0.707106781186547,0.,0.707106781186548));
#1813=DIRECTION('',(0.707106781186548,0.,0.707106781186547));
#1814=AXIS2_PLACEMENT_3D('',#1811,#1812,#1813);
#1815=PLANE('',#1814);
#1816=ORIENTED_EDGE('',*,*,#692,.F.);
#1817=ORIENTED_EDGE('',*,*,#661,.F.);
#1818=DIRECTION('',(0.707106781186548,0.,0.707106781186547));
#1819=VECTOR('',#1818,1.);
#1820=CARTESIAN_POINT('',(-26.,48.,-23.));
#1821=LINE('',#1820,#1819);
#1822=EDGE_CURVE('E828',#964,#628,#1821,.T.);
#1823=ORIENTED_EDGE('',*,*,#1822,.F.);
#1824=ORIENTED_EDGE('',*,*,#1084,.F.);
#1825=EDGE_LOOP('',(#1816,#1817,#1823,#1824));
#1826=FACE_BOUND('',#1825,.T.);
#1827=ADVANCED_FACE('F667',(#1826),#1815,.F.);
#1828=CARTESIAN_POINT('',(0.,48.,-21.));
#1829=DIRECTION('',(0.,0.,-1.));
#1830=DIRECTION('',(-1.,0.,0.));
#1831=AXIS2_PLACEMENT_3D('',#1828,#1829,#1830);
#1832=CONICAL_SURFACE('',#1831,24.,0.785398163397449);
#1833=ORIENTED_EDGE('',*,*,#1822,.T.);
#1834=ORIENTED_EDGE('',*,*,#629,.F.);
#1835=DIRECTION('',(-0.707106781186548,0.,0.707106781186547));
#1836=VECTOR('',#1835,1.);
#1837=CARTESIAN_POINT('',(26.,48.,-23.));
#1838=LINE('',#1837,#1836);
#1839=EDGE_CURVE('E826',#966,#596,#1838,.T.);
#1840=ORIENTED_EDGE('',*,*,#1839,.F.);
#1841=ORIENTED_EDGE('',*,*,#967,.F.);
#1842=EDGE_LOOP('',(#1833,#1834,#1840,#1841));
#1843=FACE_BOUND('',#1842,.T.);
#1844=ADVANCED_FACE('F671',(#1843),#1832,.F.);
#1845=CARTESIAN_POINT('',(24.,52.,-21.));
#1846=DIRECTION('',(0.707106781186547,0.,0.707106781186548));
#1847=DIRECTION('',(0.707106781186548,0.,-0.707106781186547));
#1848=AXIS2_PLACEMENT_3D('',#1845,#1846,#1847);
#1849=PLANE('',#1848);
#1850=ORIENTED_EDGE('',*,*,#557,.F.);
#1851=ORIENTED_EDGE('',*,*,#973,.F.);
#1852=ORIENTED_EDGE('',*,*,#1839,.T.);
#1853=ORIENTED_EDGE('',*,*,#597,.F.);
#1854=EDGE_LOOP('',(#1850,#1851,#1852,#1853));
#1855=FACE_BOUND('',#1854,.T.);
#1856=ADVANCED_FACE('F675',(#1855),#1849,.F.);
#1857=CARTESIAN_POINT('',(-26.,47.9999999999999,23.));
#1858=DIRECTION('',(0.707106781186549,0.,0.707106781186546));
#1859=DIRECTION('',(0.707106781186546,0.,-0.707106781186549));
#1860=AXIS2_PLACEMENT_3D('',#1857,#1858,#1859);
#1861=PLANE('',#1860);
#1862=ORIENTED_EDGE('',*,*,#722,.F.);
#1863=ORIENTED_EDGE('',*,*,#844,.F.);
#1864=DIRECTION('',(-0.707106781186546,0.,0.707106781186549));
#1865=VECTOR('',#1864,1.);
#1866=CARTESIAN_POINT('',(-24.,48.,21.));
#1867=LINE('',#1866,#1865);
#1868=EDGE_CURVE('E812',#636,#837,#1867,.T.);
#1869=ORIENTED_EDGE('',*,*,#1868,.F.);
#1870=ORIENTED_EDGE('',*,*,#675,.F.);
#1871=EDGE_LOOP('',(#1862,#1863,#1869,#1870));
#1872=FACE_BOUND('',#1871,.T.);
#1873=ADVANCED_FACE('F679',(#1872),#1861,.T.);
#1874=CARTESIAN_POINT('',(0.,48.,23.));
#1875=DIRECTION('',(0.,0.,1.));
#1876=DIRECTION('',(1.,0.,0.));
#1877=AXIS2_PLACEMENT_3D('',#1874,#1875,#1876);
#1878=CONICAL_SURFACE('',#1877,26.,0.785398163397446);
#1879=ORIENTED_EDGE('',*,*,#1868,.T.);
#1880=ORIENTED_EDGE('',*,*,#838,.F.);
#1881=DIRECTION('',(0.707106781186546,0.,0.707106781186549));
#1882=VECTOR('',#1881,1.);
#1883=CARTESIAN_POINT('',(24.,48.,21.));
#1884=LINE('',#1883,#1882);
#1885=EDGE_CURVE('E48',#604,#828,#1884,.T.);
#1886=ORIENTED_EDGE('',*,*,#1885,.F.);
#1887=ORIENTED_EDGE('',*,*,#644,.F.);
#1888=EDGE_LOOP('',(#1879,#1880,#1886,#1887));
#1889=FACE_BOUND('',#1888,.T.);
#1890=ADVANCED_FACE('F683',(#1889),#1878,.F.);
#1891=CARTESIAN_POINT('',(26.,48.,23.));
#1892=DIRECTION('',(-0.707106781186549,0.,0.707106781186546));
#1893=DIRECTION('',(0.707106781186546,0.,0.707106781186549));
#1894=AXIS2_PLACEMENT_3D('',#1891,#1892,#1893);
#1895=PLANE('',#1894);
#1896=ORIENTED_EDGE('',*,*,#573,.F.);
#1897=ORIENTED_EDGE('',*,*,#611,.F.);
#1898=ORIENTED_EDGE('',*,*,#1885,.T.);
#1899=ORIENTED_EDGE('',*,*,#829,.F.);
#1900=EDGE_LOOP('',(#1896,#1897,#1898,#1899));
#1901=FACE_BOUND('',#1900,.T.);
#1902=ADVANCED_FACE('F687',(#1901),#1895,.T.);
#1903=CLOSED_SHELL('',(#198,#250,#302,#342,#407,#438,#506,#537,#584,#615,#648,#679,#726,#748,
#816,#952,#1088,#1106,#1124,#1146,#1163,#1180,#1192,#1223,#1247,#1271,#1288,#1311,#1342,#1366,
#1390,#1407,#1430,#1442,#1454,#1486,#1510,#1535,#1552,#1584,#1608,#1633,#1650,#1662,#1674,#1696,
#1713,#1730,#1742,#1764,#1781,#1798,#1810,#1827,#1844,#1856,#1873,#1890,#1902));
#1904=MANIFOLD_SOLID_BREP('B2',#1903);
#1905=ADVANCED_BREP_SHAPE_REPRESENTATION('',(#18,#1904),#14);
#1906=SHAPE_DEFINITION_REPRESENTATION(#9,#1905);
ENDSEC;
END-ISO-10303-21;
